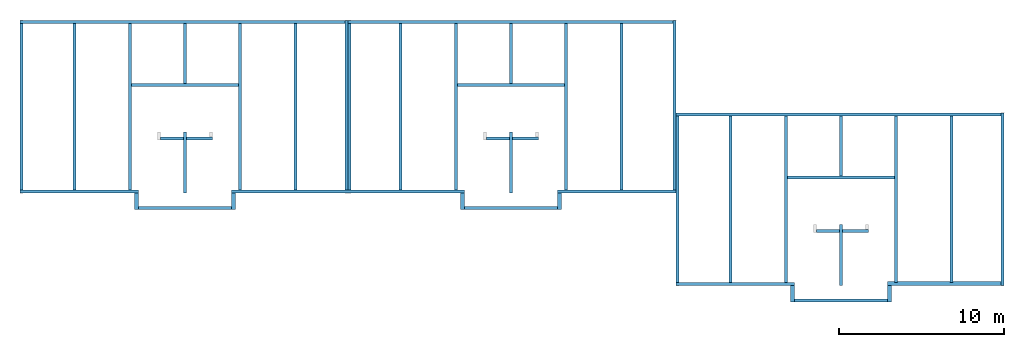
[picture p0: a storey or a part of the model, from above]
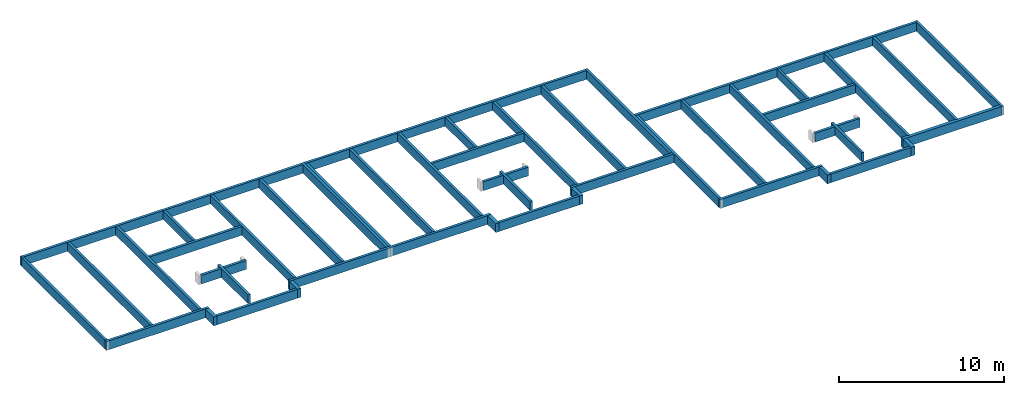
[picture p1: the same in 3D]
Properties of the parts of a building model (IFC2X3), part 1 of 3

# File
Description: IFC2x3 Coordination View
File name: C:\Users\jean-pierre\Desktop\acqs 2016.ifc
Time: 2016-04-21T13:30:04
Author: jean-pierre lafourcade
Organization: Nemetschek AG, Konrad-Zuse-Platz 1, 81829 Munich / Germany
Written by: The EXPRESS Data Manager Version 5.02.0100.02 : 29 May 2013
Made in: Allplan 2015.1 31.03.2015 - 10:33:38

# IfcBuildingStorey (5)
In: Bâtiment
Name | Elevation (mm)
vs | -850
rdc | 0
r+1 | 2700
r+2 | 5400
r+3 | 8100

# IfcOpeningElement: Opening (161)
Allplan Attributes - Object Layer Attributes #1, Catégorie de transformation: Nouvelle construction; Object Layer Attributes #1, Unité: m²
Name | In | Length (m) | Height (m) | GrossVolume (m3) | NominalArea (m2) | Object Layer Attributes #1, Métier = Object Layer Attributes #2, Métier | Object Layer Attributes #1, NOI_UUID | Object Layer Attributes #2, Unité = Object Layer Attributes #3, Unité | Object Layer Attributes #2, NOI_UUID | Object Layer Attributes #3, Métier | Object Layer Attributes #3, NOI_UUID
Baie de fenêtre | rdc | 0.6 | 0.34 | -0.03672 | -0.204 | Maçonnerie | 938c77c7-219d-4147-869d-5d58a54f96e7--5496 | m² | 938c77c7-219d-4147-869d-5d58a54f96e7--5497 | Enduits et plâtrages | 938c77c7-219d-4147-869d-5d58a54f96e7--5498
Baie de fenêtre | rdc | 0.6 | 0.34 | -0.03672 | -0.204 | Maçonnerie | 938c77c7-219d-4147-869d-5d58a54f96e7--5516 | m² | 938c77c7-219d-4147-869d-5d58a54f96e7--5517 | Enduits et plâtrages | 938c77c7-219d-4147-869d-5d58a54f96e7--5518
Baie de fenêtre | rdc | 1.8 | 1.15 | -0.3726 | -2.07 | Maçonnerie | 938c77c7-219d-4147-869d-5d58a54f96e7--5156 | m² | 938c77c7-219d-4147-869d-5d58a54f96e7--5157 | Enduits et plâtrages | 938c77c7-219d-4147-869d-5d58a54f96e7--5158
Baie de fenêtre | rdc | 1.8 | 1.15 | -0.3726 | -2.07 | Maçonnerie | 938c77c7-219d-4147-869d-5d58a54f96e7--5176 | m² | 938c77c7-219d-4147-869d-5d58a54f96e7--5177 | Enduits et plâtrages | 938c77c7-219d-4147-869d-5d58a54f96e7--5178
Baie de fenêtre | rdc | 1.8 | 1.15 | -0.3726 | -2.07 | Maçonnerie | 938c77c7-219d-4147-869d-5d58a54f96e7--5196 | m² | 938c77c7-219d-4147-869d-5d58a54f96e7--5197 | Enduits et plâtrages | 938c77c7-219d-4147-869d-5d58a54f96e7--5198
Baie de fenêtre | rdc | 1.8 | 1.15 | -0.3726 | -2.07 | Maçonnerie | 938c77c7-219d-4147-869d-5d58a54f96e7--5216 | m² | 938c77c7-219d-4147-869d-5d58a54f96e7--5217 | Enduits et plâtrages | 938c77c7-219d-4147-869d-5d58a54f96e7--5218
Baie de porte | rdc | 2.9 | 2.15 | -1.1223 | -6.235 | Maçonnerie | 938c77c7-219d-4147-869d-5d58a54f96e7--5356 | m² | 938c77c7-219d-4147-869d-5d58a54f96e7--5357 | Enduits et plâtrages | 938c77c7-219d-4147-869d-5d58a54f96e7--5358
Baie de porte | rdc | 2.9 | 2.15 | -1.1223 | -6.235 | Maçonnerie | 938c77c7-219d-4147-869d-5d58a54f96e7--5376 | m² | 938c77c7-219d-4147-869d-5d58a54f96e7--5377 | Enduits et plâtrages | 938c77c7-219d-4147-869d-5d58a54f96e7--5378
Baie de fenêtre | rdc | 1.8 | 1.15 | -0.3726 | -2.07 | Maçonnerie | 938c77c7-219d-4147-869d-5d58a54f96e7--5076 | m² | 938c77c7-219d-4147-869d-5d58a54f96e7--5077 | Enduits et plâtrages | 938c77c7-219d-4147-869d-5d58a54f96e7--5078
Baie de fenêtre | rdc | 1.8 | 1.15 | -0.3726 | -2.07 | Maçonnerie | 938c77c7-219d-4147-869d-5d58a54f96e7--5096 | m² | 938c77c7-219d-4147-869d-5d58a54f96e7--5097 | Enduits et plâtrages | 938c77c7-219d-4147-869d-5d58a54f96e7--5098
Baie de fenêtre | rdc | 1.8 | 1.15 | -0.3726 | -2.07 | Maçonnerie | 938c77c7-219d-4147-869d-5d58a54f96e7--5116 | m² | 938c77c7-219d-4147-869d-5d58a54f96e7--5117 | Enduits et plâtrages | 938c77c7-219d-4147-869d-5d58a54f96e7--5118
Baie de fenêtre | rdc | 1.8 | 1.15 | -0.3726 | -2.07 | Maçonnerie | 938c77c7-219d-4147-869d-5d58a54f96e7--5136 | m² | 938c77c7-219d-4147-869d-5d58a54f96e7--5137 | Enduits et plâtrages | 938c77c7-219d-4147-869d-5d58a54f96e7--5138
Baie de porte | rdc | 2.9 | 2.15 | -1.1223 | -6.235 | Maçonnerie | 938c77c7-219d-4147-869d-5d58a54f96e7--5316 | m² | 938c77c7-219d-4147-869d-5d58a54f96e7--5317 | Enduits et plâtrages | 938c77c7-219d-4147-869d-5d58a54f96e7--5318
Baie de porte | rdc | 2.9 | 2.15 | -1.1223 | -6.235 | Maçonnerie | 938c77c7-219d-4147-869d-5d58a54f96e7--5336 | m² | 938c77c7-219d-4147-869d-5d58a54f96e7--5337 | Enduits et plâtrages | 938c77c7-219d-4147-869d-5d58a54f96e7--5338
Baie de fenêtre | rdc | 1.8 | 1.15 | -0.3726 | -2.07 | Maçonnerie | 938c77c7-219d-4147-869d-5d58a54f96e7--5236 | m² | 938c77c7-219d-4147-869d-5d58a54f96e7--5237 | Enduits et plâtrages | 938c77c7-219d-4147-869d-5d58a54f96e7--5238
Baie de fenêtre | rdc | 1.8 | 1.15 | -0.3726 | -2.07 | Maçonnerie | 938c77c7-219d-4147-869d-5d58a54f96e7--5256 | m² | 938c77c7-219d-4147-869d-5d58a54f96e7--5257 | Enduits et plâtrages | 938c77c7-219d-4147-869d-5d58a54f96e7--5258
Baie de fenêtre | rdc | 1.8 | 1.15 | -0.3726 | -2.07 | Maçonnerie | 938c77c7-219d-4147-869d-5d58a54f96e7--5276 | m² | 938c77c7-219d-4147-869d-5d58a54f96e7--5277 | Enduits et plâtrages | 938c77c7-219d-4147-869d-5d58a54f96e7--5278
Baie de fenêtre | rdc | 1.8 | 1.15 | -0.3726 | -2.07 | Maçonnerie | 938c77c7-219d-4147-869d-5d58a54f96e7--5296 | m² | 938c77c7-219d-4147-869d-5d58a54f96e7--5297 | Enduits et plâtrages | 938c77c7-219d-4147-869d-5d58a54f96e7--5298
Baie de porte | rdc | 2.9 | 2.15 | -1.1223 | -6.235 | Maçonnerie | 938c77c7-219d-4147-869d-5d58a54f96e7--5396 | m² | 938c77c7-219d-4147-869d-5d58a54f96e7--5397 | Enduits et plâtrages | 938c77c7-219d-4147-869d-5d58a54f96e7--5398
Baie de porte | rdc | 2.9 | 2.15 | -1.1223 | -6.235 | Maçonnerie | 938c77c7-219d-4147-869d-5d58a54f96e7--5416 | m² | 938c77c7-219d-4147-869d-5d58a54f96e7--5417 | Enduits et plâtrages | 938c77c7-219d-4147-869d-5d58a54f96e7--5418
Baie de fenêtre | rdc | 1.8 | 1.15 | -0.3726 | -2.07 | Maçonnerie | 938c77c7-219d-4147-869d-5d58a54f96e7--4283 | m² | 938c77c7-219d-4147-869d-5d58a54f96e7--4284 | Enduits et plâtrages | 938c77c7-219d-4147-869d-5d58a54f96e7--4285
Baie de fenêtre | rdc | 1.8 | 1.15 | -0.3726 | -2.07 | Maçonnerie | 938c77c7-219d-4147-869d-5d58a54f96e7--4303 | m² | 938c77c7-219d-4147-869d-5d58a54f96e7--4304 | Enduits et plâtrages | 938c77c7-219d-4147-869d-5d58a54f96e7--4305
Baie de fenêtre | rdc | 0.6 | 0.34 | -0.03672 | -0.204 | Maçonnerie | 938c77c7-219d-4147-869d-5d58a54f96e7--5476 | m² | 938c77c7-219d-4147-869d-5d58a54f96e7--5477 | Enduits et plâtrages | 938c77c7-219d-4147-869d-5d58a54f96e7--5478
Baie de fenêtre | rdc | 1.3 | 0.34 | -0.07956 | -0.442 | Maçonnerie | 938c77c7-219d-4147-869d-5d58a54f96e7--5576 | m² | 938c77c7-219d-4147-869d-5d58a54f96e7--5577 | Enduits et plâtrages | 938c77c7-219d-4147-869d-5d58a54f96e7--5578
Baie de fenêtre | rdc | 1.8 | 1.15 | -0.3726 | -2.07 | Maçonnerie | 938c77c7-219d-4147-869d-5d58a54f96e7--4323 | m² | 938c77c7-219d-4147-869d-5d58a54f96e7--4324 | Enduits et plâtrages | 938c77c7-219d-4147-869d-5d58a54f96e7--4325
Baie de fenêtre | rdc | 1.8 | 1.15 | -0.3726 | -2.07 | Maçonnerie | 938c77c7-219d-4147-869d-5d58a54f96e7--4343 | m² | 938c77c7-219d-4147-869d-5d58a54f96e7--4344 | Enduits et plâtrages | 938c77c7-219d-4147-869d-5d58a54f96e7--4345
Baie de fenêtre | rdc | 1.8 | 1.15 | -0.3726 | -2.07 | Maçonnerie | 938c77c7-219d-4147-869d-5d58a54f96e7--4363 | m² | 938c77c7-219d-4147-869d-5d58a54f96e7--4364 | Enduits et plâtrages | 938c77c7-219d-4147-869d-5d58a54f96e7--4365
Baie de fenêtre | rdc | 1.8 | 1.15 | -0.3726 | -2.07 | Maçonnerie | 938c77c7-219d-4147-869d-5d58a54f96e7--5035 | m² | 938c77c7-219d-4147-869d-5d58a54f96e7--5036 | Enduits et plâtrages | 938c77c7-219d-4147-869d-5d58a54f96e7--5037
Baie de fenêtre | rdc | 1.8 | 1.15 | -0.3726 | -2.07 | Maçonnerie | 938c77c7-219d-4147-869d-5d58a54f96e7--5056 | m² | 938c77c7-219d-4147-869d-5d58a54f96e7--5057 | Enduits et plâtrages | 938c77c7-219d-4147-869d-5d58a54f96e7--5058
Baie de fenêtre | rdc | 0.6 | 0.34 | -0.03672 | -0.204 | Maçonnerie | 938c77c7-219d-4147-869d-5d58a54f96e7--5536 | m² | 938c77c7-219d-4147-869d-5d58a54f96e7--5537 | Enduits et plâtrages | 938c77c7-219d-4147-869d-5d58a54f96e7--5538
Baie de fenêtre | rdc | 1.3 | 0.34 | -0.07956 | -0.442 | Maçonnerie | 938c77c7-219d-4147-869d-5d58a54f96e7--5556 | m² | 938c77c7-219d-4147-869d-5d58a54f96e7--5557 | Enduits et plâtrages | 938c77c7-219d-4147-869d-5d58a54f96e7--5558
Baie de fenêtre | rdc | 0.6 | 0.34 | -0.03672 | -0.204 | Maçonnerie | 938c77c7-219d-4147-869d-5d58a54f96e7--5436 | m² | 938c77c7-219d-4147-869d-5d58a54f96e7--5437 | Enduits et plâtrages | 938c77c7-219d-4147-869d-5d58a54f96e7--5438
Baie de fenêtre | rdc | 0.6 | 0.34 | -0.03672 | -0.204 | Maçonnerie | 938c77c7-219d-4147-869d-5d58a54f96e7--5456 | m² | 938c77c7-219d-4147-869d-5d58a54f96e7--5457 | Enduits et plâtrages | 938c77c7-219d-4147-869d-5d58a54f96e7--5458
Baie de fenêtre | rdc | 1.8 | 1.15 | -0.3726 | -2.07 | Maçonnerie | 938c77c7-219d-4147-869d-5d58a54f96e7--4421 | m² | 938c77c7-219d-4147-869d-5d58a54f96e7--4422 | Enduits et plâtrages | 938c77c7-219d-4147-869d-5d58a54f96e7--4423
Baie de fenêtre | rdc | 1.8 | 1.15 | -0.3726 | -2.07 | Maçonnerie | 938c77c7-219d-4147-869d-5d58a54f96e7--4441 | m² | 938c77c7-219d-4147-869d-5d58a54f96e7--4442 | Enduits et plâtrages | 938c77c7-219d-4147-869d-5d58a54f96e7--4443
Baie de fenêtre | rdc | 1.8 | 1.15 | -0.3726 | -2.07 | Maçonnerie | 938c77c7-219d-4147-869d-5d58a54f96e7--4823 | m² | 938c77c7-219d-4147-869d-5d58a54f96e7--4824 | Enduits et plâtrages | 938c77c7-219d-4147-869d-5d58a54f96e7--4825
Baie de fenêtre | rdc | 1.8 | 1.15 | -0.3726 | -2.07 | Maçonnerie | 938c77c7-219d-4147-869d-5d58a54f96e7--4481 | m² | 938c77c7-219d-4147-869d-5d58a54f96e7--4482 | Enduits et plâtrages | 938c77c7-219d-4147-869d-5d58a54f96e7--4483
Baie de fenêtre | rdc | 1.8 | 1.15 | -0.3726 | -2.07 | Maçonnerie | 938c77c7-219d-4147-869d-5d58a54f96e7--4461 | m² | 938c77c7-219d-4147-869d-5d58a54f96e7--4462 | Enduits et plâtrages | 938c77c7-219d-4147-869d-5d58a54f96e7--4463
Baie de fenêtre | r+1 | 0.6 | 0.34 | -0.03672 | -0.204 | Maçonnerie | d80b2029-7616-407a-9da1-afa361a85c10--1853 | m² | d80b2029-7616-407a-9da1-afa361a85c10--1852 | Enduits et plâtrages | d80b2029-7616-407a-9da1-afa361a85c10--1851
Baie de fenêtre | r+1 | 0.6 | 0.34 | -0.03672 | -0.204 | Maçonnerie | d80b2029-7616-407a-9da1-afa361a85c10--1859 | m² | d80b2029-7616-407a-9da1-afa361a85c10--1858 | Enduits et plâtrages | d80b2029-7616-407a-9da1-afa361a85c10--1857
Baie de fenêtre | r+1 | 1.8 | 1.15 | -0.3726 | -2.07 | Maçonnerie | d80b2029-7616-407a-9da1-afa361a85c10--1739 | m² | d80b2029-7616-407a-9da1-afa361a85c10--1738 | Enduits et plâtrages | d80b2029-7616-407a-9da1-afa361a85c10--1737
Baie de fenêtre | r+1 | 1.8 | 1.15 | -0.3726 | -2.07 | Maçonnerie | d80b2029-7616-407a-9da1-afa361a85c10--1745 | m² | d80b2029-7616-407a-9da1-afa361a85c10--1744 | Enduits et plâtrages | d80b2029-7616-407a-9da1-afa361a85c10--1743
Baie de fenêtre | r+1 | 1.8 | 1.15 | -0.3726 | -2.07 | Maçonnerie | d80b2029-7616-407a-9da1-afa361a85c10--1751 | m² | d80b2029-7616-407a-9da1-afa361a85c10--1750 | Enduits et plâtrages | d80b2029-7616-407a-9da1-afa361a85c10--1749
Baie de fenêtre | r+1 | 1.8 | 1.15 | -0.3726 | -2.07 | Maçonnerie | d80b2029-7616-407a-9da1-afa361a85c10--1757 | m² | d80b2029-7616-407a-9da1-afa361a85c10--1756 | Enduits et plâtrages | d80b2029-7616-407a-9da1-afa361a85c10--1755
Baie de porte | r+1 | 2.9 | 2.15 | -1.1223 | -6.235 | Maçonnerie | d80b2029-7616-407a-9da1-afa361a85c10--1802 | m² | d80b2029-7616-407a-9da1-afa361a85c10--1801 | Enduits et plâtrages | d80b2029-7616-407a-9da1-afa361a85c10--1800
Baie de porte | r+1 | 2.9 | 2.15 | -1.1223 | -6.235 | Maçonnerie | d80b2029-7616-407a-9da1-afa361a85c10--1808 | m² | d80b2029-7616-407a-9da1-afa361a85c10--1807 | Enduits et plâtrages | d80b2029-7616-407a-9da1-afa361a85c10--1806
Baie de fenêtre | r+1 | 1.8 | 1.15 | -0.3726 | -2.07 | Maçonnerie | d80b2029-7616-407a-9da1-afa361a85c10--1715 | m² | d80b2029-7616-407a-9da1-afa361a85c10--1714 | Enduits et plâtrages | d80b2029-7616-407a-9da1-afa361a85c10--1713
Baie de fenêtre | r+1 | 1.8 | 1.15 | -0.3726 | -2.07 | Maçonnerie | d80b2029-7616-407a-9da1-afa361a85c10--1721 | m² | d80b2029-7616-407a-9da1-afa361a85c10--1720 | Enduits et plâtrages | d80b2029-7616-407a-9da1-afa361a85c10--1719
Baie de fenêtre | r+1 | 1.8 | 1.15 | -0.3726 | -2.07 | Maçonnerie | d80b2029-7616-407a-9da1-afa361a85c10--1727 | m² | d80b2029-7616-407a-9da1-afa361a85c10--1726 | Enduits et plâtrages | d80b2029-7616-407a-9da1-afa361a85c10--1725
Baie de fenêtre | r+1 | 1.8 | 1.15 | -0.3726 | -2.07 | Maçonnerie | d80b2029-7616-407a-9da1-afa361a85c10--1733 | m² | d80b2029-7616-407a-9da1-afa361a85c10--1732 | Enduits et plâtrages | d80b2029-7616-407a-9da1-afa361a85c10--1731
Baie de porte | r+1 | 2.9 | 2.15 | -1.1223 | -6.235 | Maçonnerie | d80b2029-7616-407a-9da1-afa361a85c10--1787 | m² | d80b2029-7616-407a-9da1-afa361a85c10--1786 | Enduits et plâtrages | d80b2029-7616-407a-9da1-afa361a85c10--1785
Baie de porte | r+1 | 2.9 | 2.15 | -1.1223 | -6.235 | Maçonnerie | d80b2029-7616-407a-9da1-afa361a85c10--1793 | m² | d80b2029-7616-407a-9da1-afa361a85c10--1792 | Enduits et plâtrages | d80b2029-7616-407a-9da1-afa361a85c10--1791
Baie de fenêtre | r+1 | 1.8 | 1.15 | -0.3726 | -2.07 | Maçonnerie | d80b2029-7616-407a-9da1-afa361a85c10--1763 | m² | d80b2029-7616-407a-9da1-afa361a85c10--1762 | Enduits et plâtrages | d80b2029-7616-407a-9da1-afa361a85c10--1761
Baie de fenêtre | r+1 | 1.8 | 1.15 | -0.3726 | -2.07 | Maçonnerie | d80b2029-7616-407a-9da1-afa361a85c10--1769 | m² | d80b2029-7616-407a-9da1-afa361a85c10--1768 | Enduits et plâtrages | d80b2029-7616-407a-9da1-afa361a85c10--1767
Baie de fenêtre | r+1 | 1.8 | 1.15 | -0.3726 | -2.07 | Maçonnerie | d80b2029-7616-407a-9da1-afa361a85c10--1775 | m² | d80b2029-7616-407a-9da1-afa361a85c10--1774 | Enduits et plâtrages | d80b2029-7616-407a-9da1-afa361a85c10--1773
Baie de fenêtre | r+1 | 1.8 | 1.15 | -0.3726 | -2.07 | Maçonnerie | d80b2029-7616-407a-9da1-afa361a85c10--1781 | m² | d80b2029-7616-407a-9da1-afa361a85c10--1780 | Enduits et plâtrages | d80b2029-7616-407a-9da1-afa361a85c10--1779
Baie de porte | r+1 | 2.9 | 2.15 | -1.1223 | -6.235 | Maçonnerie | d80b2029-7616-407a-9da1-afa361a85c10--1817 | m² | d80b2029-7616-407a-9da1-afa361a85c10--1816 | Enduits et plâtrages | d80b2029-7616-407a-9da1-afa361a85c10--1815
Baie de porte | r+1 | 2.9 | 2.15 | -1.1223 | -6.235 | Maçonnerie | d80b2029-7616-407a-9da1-afa361a85c10--1823 | m² | d80b2029-7616-407a-9da1-afa361a85c10--1822 | Enduits et plâtrages | d80b2029-7616-407a-9da1-afa361a85c10--1821
Baie de fenêtre | r+1 | 0.6 | 0.34 | -0.03672 | -0.204 | Maçonnerie | d80b2029-7616-407a-9da1-afa361a85c10--1847 | m² | d80b2029-7616-407a-9da1-afa361a85c10--1846 | Enduits et plâtrages | d80b2029-7616-407a-9da1-afa361a85c10--1845
Baie de fenêtre | r+1 | 1.3 | 0.34 | -0.07956 | -0.442 | Maçonnerie | d80b2029-7616-407a-9da1-afa361a85c10--1883 | m² | d80b2029-7616-407a-9da1-afa361a85c10--1882 | Enduits et plâtrages | d80b2029-7616-407a-9da1-afa361a85c10--1881
Baie de fenêtre | r+1 | 1.8 | 1.15 | -0.3726 | -2.07 | Maçonnerie | d80b2029-7616-407a-9da1-afa361a85c10--1555 | m² | d80b2029-7616-407a-9da1-afa361a85c10--1554 | Enduits et plâtrages | d80b2029-7616-407a-9da1-afa361a85c10--1553
Baie de fenêtre | r+1 | 1.8 | 1.15 | -0.3726 | -2.07 | Maçonnerie | d80b2029-7616-407a-9da1-afa361a85c10--1561 | m² | d80b2029-7616-407a-9da1-afa361a85c10--1560 | Enduits et plâtrages | d80b2029-7616-407a-9da1-afa361a85c10--1559
Baie de fenêtre | r+1 | 1.8 | 1.15 | -0.3726 | -2.07 | Maçonnerie | d80b2029-7616-407a-9da1-afa361a85c10--1567 | m² | d80b2029-7616-407a-9da1-afa361a85c10--1566 | Enduits et plâtrages | d80b2029-7616-407a-9da1-afa361a85c10--1565
Baie de fenêtre | r+1 | 1.8 | 1.15 | -0.3726 | -2.07 | Maçonnerie | d80b2029-7616-407a-9da1-afa361a85c10--1700 | m² | d80b2029-7616-407a-9da1-afa361a85c10--1699 | Enduits et plâtrages | d80b2029-7616-407a-9da1-afa361a85c10--1698
Baie de fenêtre | r+1 | 1.8 | 1.15 | -0.3726 | -2.07 | Maçonnerie | d80b2029-7616-407a-9da1-afa361a85c10--1709 | m² | d80b2029-7616-407a-9da1-afa361a85c10--1708 | Enduits et plâtrages | d80b2029-7616-407a-9da1-afa361a85c10--1707
Baie de fenêtre | r+1 | 0.6 | 0.34 | -0.03672 | -0.204 | Maçonnerie | d80b2029-7616-407a-9da1-afa361a85c10--1868 | m² | d80b2029-7616-407a-9da1-afa361a85c10--1867 | Enduits et plâtrages | d80b2029-7616-407a-9da1-afa361a85c10--1866
Baie de fenêtre | r+1 | 1.3 | 0.34 | -0.07956 | -0.442 | Maçonnerie | d80b2029-7616-407a-9da1-afa361a85c10--1874 | m² | d80b2029-7616-407a-9da1-afa361a85c10--1873 | Enduits et plâtrages | d80b2029-7616-407a-9da1-afa361a85c10--1872
Baie de fenêtre | r+1 | 0.6 | 0.34 | -0.03672 | -0.204 | Maçonnerie | d80b2029-7616-407a-9da1-afa361a85c10--1832 | m² | d80b2029-7616-407a-9da1-afa361a85c10--1831 | Enduits et plâtrages | d80b2029-7616-407a-9da1-afa361a85c10--1830
Baie de fenêtre | r+1 | 0.6 | 0.34 | -0.03672 | -0.204 | Maçonnerie | d80b2029-7616-407a-9da1-afa361a85c10--1838 | m² | d80b2029-7616-407a-9da1-afa361a85c10--1837 | Enduits et plâtrages | d80b2029-7616-407a-9da1-afa361a85c10--1836
Baie de fenêtre | r+1 | 1.8 | 1.15 | -0.3726 | -2.07 | Maçonnerie | d80b2029-7616-407a-9da1-afa361a85c10--1576 | m² | d80b2029-7616-407a-9da1-afa361a85c10--1575 | Enduits et plâtrages | d80b2029-7616-407a-9da1-afa361a85c10--1574
Baie de fenêtre | r+1 | 1.8 | 1.15 | -0.3726 | -2.07 | Maçonnerie | d80b2029-7616-407a-9da1-afa361a85c10--1582 | m² | d80b2029-7616-407a-9da1-afa361a85c10--1581 | Enduits et plâtrages | d80b2029-7616-407a-9da1-afa361a85c10--1580
Baie de fenêtre | r+1 | 1.8 | 1.15 | -0.3726 | -2.07 | Maçonnerie | d80b2029-7616-407a-9da1-afa361a85c10--1689 | m² | d80b2029-7616-407a-9da1-afa361a85c10--1690 | Enduits et plâtrages | d80b2029-7616-407a-9da1-afa361a85c10--1691
Baie de fenêtre | r+1 | 1.8 | 1.15 | -0.3726 | -2.07 | Maçonnerie | d80b2029-7616-407a-9da1-afa361a85c10--1666 | m² | d80b2029-7616-407a-9da1-afa361a85c10--1665 | Enduits et plâtrages | d80b2029-7616-407a-9da1-afa361a85c10--1664
Baie de fenêtre | r+1 | 1.8 | 1.15 | -0.3726 | -2.07 | Maçonnerie | d80b2029-7616-407a-9da1-afa361a85c10--1680 | m² | d80b2029-7616-407a-9da1-afa361a85c10--1681 | Enduits et plâtrages | d80b2029-7616-407a-9da1-afa361a85c10--1682
Baie de fenêtre | r+1 | 1.8 | 1.15 | -0.3726 | -2.07 | Maçonnerie | d80b2029-7616-407a-9da1-afa361a85c10--1546 | m² | d80b2029-7616-407a-9da1-afa361a85c10--1545 | Enduits et plâtrages | d80b2029-7616-407a-9da1-afa361a85c10--1544
Baie de fenêtre | r+1 | 1.8 | 1.15 | -0.3726 | -2.07 | Maçonnerie | d80b2029-7616-407a-9da1-afa361a85c10--1540 | m² | d80b2029-7616-407a-9da1-afa361a85c10--1539 | Enduits et plâtrages | d80b2029-7616-407a-9da1-afa361a85c10--1538
Trémie dans dalle | r+1 | 4.05 | 0.2 | -1.2555 | -6.2775 |  | d80b2029-7616-407a-9da1-afa361a85c10--641
Trémie dans dalle | r+1 | 4.05 | 0.2 | -1.2555 | -6.2775 |  | d80b2029-7616-407a-9da1-afa361a85c10--575
Trémie dans dalle | r+1 | 4.05 | 0.2 | -1.2555 | -6.2775 |  | d80b2029-7616-407a-9da1-afa361a85c10--580
Baie de fenêtre | r+2 | 0.6 | 0.34 | -0.03672 | -0.204 | Maçonnerie | 25afd9b5-9bbd-43b9-8fed-22435f7cc0c3--1191 | m² | 25afd9b5-9bbd-43b9-8fed-22435f7cc0c3--1190 | Enduits et plâtrages | 25afd9b5-9bbd-43b9-8fed-22435f7cc0c3--1189
Baie de fenêtre | r+2 | 0.6 | 0.34 | -0.03672 | -0.204 | Maçonnerie | 25afd9b5-9bbd-43b9-8fed-22435f7cc0c3--1194 | m² | 25afd9b5-9bbd-43b9-8fed-22435f7cc0c3--1193 | Enduits et plâtrages | 25afd9b5-9bbd-43b9-8fed-22435f7cc0c3--1192
Baie de fenêtre | r+2 | 1.8 | 1.15 | -0.3726 | -2.07 | Maçonnerie | 25afd9b5-9bbd-43b9-8fed-22435f7cc0c3--1140 | m² | 25afd9b5-9bbd-43b9-8fed-22435f7cc0c3--1139 | Enduits et plâtrages | 25afd9b5-9bbd-43b9-8fed-22435f7cc0c3--1138
Baie de fenêtre | r+2 | 1.8 | 1.15 | -0.3726 | -2.07 | Maçonnerie | 25afd9b5-9bbd-43b9-8fed-22435f7cc0c3--1143 | m² | 25afd9b5-9bbd-43b9-8fed-22435f7cc0c3--1142 | Enduits et plâtrages | 25afd9b5-9bbd-43b9-8fed-22435f7cc0c3--1141
Baie de fenêtre | r+2 | 1.8 | 1.15 | -0.3726 | -2.07 | Maçonnerie | 25afd9b5-9bbd-43b9-8fed-22435f7cc0c3--1146 | m² | 25afd9b5-9bbd-43b9-8fed-22435f7cc0c3--1145 | Enduits et plâtrages | 25afd9b5-9bbd-43b9-8fed-22435f7cc0c3--1144
Baie de fenêtre | r+2 | 1.8 | 1.15 | -0.3726 | -2.07 | Maçonnerie | 25afd9b5-9bbd-43b9-8fed-22435f7cc0c3--1149 | m² | 25afd9b5-9bbd-43b9-8fed-22435f7cc0c3--1148 | Enduits et plâtrages | 25afd9b5-9bbd-43b9-8fed-22435f7cc0c3--1147
Baie de porte | r+2 | 2.9 | 2.15 | -1.1223 | -6.235 | Maçonnerie | 25afd9b5-9bbd-43b9-8fed-22435f7cc0c3--1170 | m² | 25afd9b5-9bbd-43b9-8fed-22435f7cc0c3--1169 | Enduits et plâtrages | 25afd9b5-9bbd-43b9-8fed-22435f7cc0c3--1168
Baie de porte | r+2 | 2.9 | 2.15 | -1.1223 | -6.235 | Maçonnerie | 25afd9b5-9bbd-43b9-8fed-22435f7cc0c3--1173 | m² | 25afd9b5-9bbd-43b9-8fed-22435f7cc0c3--1172 | Enduits et plâtrages | 25afd9b5-9bbd-43b9-8fed-22435f7cc0c3--1171
Baie de fenêtre | r+2 | 1.8 | 1.15 | -0.3726 | -2.07 | Maçonnerie | 25afd9b5-9bbd-43b9-8fed-22435f7cc0c3--1128 | m² | 25afd9b5-9bbd-43b9-8fed-22435f7cc0c3--1127 | Enduits et plâtrages | 25afd9b5-9bbd-43b9-8fed-22435f7cc0c3--1126
Baie de fenêtre | r+2 | 1.8 | 1.15 | -0.3726 | -2.07 | Maçonnerie | 25afd9b5-9bbd-43b9-8fed-22435f7cc0c3--1131 | m² | 25afd9b5-9bbd-43b9-8fed-22435f7cc0c3--1130 | Enduits et plâtrages | 25afd9b5-9bbd-43b9-8fed-22435f7cc0c3--1129
Baie de fenêtre | r+2 | 1.8 | 1.15 | -0.3726 | -2.07 | Maçonnerie | 25afd9b5-9bbd-43b9-8fed-22435f7cc0c3--1134 | m² | 25afd9b5-9bbd-43b9-8fed-22435f7cc0c3--1133 | Enduits et plâtrages | 25afd9b5-9bbd-43b9-8fed-22435f7cc0c3--1132
Baie de fenêtre | r+2 | 1.8 | 1.15 | -0.3726 | -2.07 | Maçonnerie | 25afd9b5-9bbd-43b9-8fed-22435f7cc0c3--1137 | m² | 25afd9b5-9bbd-43b9-8fed-22435f7cc0c3--1136 | Enduits et plâtrages | 25afd9b5-9bbd-43b9-8fed-22435f7cc0c3--1135
Baie de porte | r+2 | 2.9 | 2.15 | -1.1223 | -6.235 | Maçonnerie | 25afd9b5-9bbd-43b9-8fed-22435f7cc0c3--1164 | m² | 25afd9b5-9bbd-43b9-8fed-22435f7cc0c3--1163 | Enduits et plâtrages | 25afd9b5-9bbd-43b9-8fed-22435f7cc0c3--1162
Baie de porte | r+2 | 2.9 | 2.15 | -1.1223 | -6.235 | Maçonnerie | 25afd9b5-9bbd-43b9-8fed-22435f7cc0c3--1167 | m² | 25afd9b5-9bbd-43b9-8fed-22435f7cc0c3--1166 | Enduits et plâtrages | 25afd9b5-9bbd-43b9-8fed-22435f7cc0c3--1165
Baie de fenêtre | r+2 | 1.8 | 1.15 | -0.3726 | -2.07 | Maçonnerie | 25afd9b5-9bbd-43b9-8fed-22435f7cc0c3--1152 | m² | 25afd9b5-9bbd-43b9-8fed-22435f7cc0c3--1151 | Enduits et plâtrages | 25afd9b5-9bbd-43b9-8fed-22435f7cc0c3--1150
Baie de fenêtre | r+2 | 1.8 | 1.15 | -0.3726 | -2.07 | Maçonnerie | 25afd9b5-9bbd-43b9-8fed-22435f7cc0c3--1155 | m² | 25afd9b5-9bbd-43b9-8fed-22435f7cc0c3--1154 | Enduits et plâtrages | 25afd9b5-9bbd-43b9-8fed-22435f7cc0c3--1153
Baie de fenêtre | r+2 | 1.8 | 1.15 | -0.3726 | -2.07 | Maçonnerie | 25afd9b5-9bbd-43b9-8fed-22435f7cc0c3--1158 | m² | 25afd9b5-9bbd-43b9-8fed-22435f7cc0c3--1157 | Enduits et plâtrages | 25afd9b5-9bbd-43b9-8fed-22435f7cc0c3--1156
Baie de fenêtre | r+2 | 1.8 | 1.15 | -0.3726 | -2.07 | Maçonnerie | 25afd9b5-9bbd-43b9-8fed-22435f7cc0c3--1161 | m² | 25afd9b5-9bbd-43b9-8fed-22435f7cc0c3--1160 | Enduits et plâtrages | 25afd9b5-9bbd-43b9-8fed-22435f7cc0c3--1159
Baie de porte | r+2 | 2.9 | 2.15 | -1.1223 | -6.235 | Maçonnerie | 25afd9b5-9bbd-43b9-8fed-22435f7cc0c3--1176 | m² | 25afd9b5-9bbd-43b9-8fed-22435f7cc0c3--1175 | Enduits et plâtrages | 25afd9b5-9bbd-43b9-8fed-22435f7cc0c3--1174
Baie de porte | r+2 | 2.9 | 2.15 | -1.1223 | -6.235 | Maçonnerie | 25afd9b5-9bbd-43b9-8fed-22435f7cc0c3--1179 | m² | 25afd9b5-9bbd-43b9-8fed-22435f7cc0c3--1178 | Enduits et plâtrages | 25afd9b5-9bbd-43b9-8fed-22435f7cc0c3--1177
Baie de fenêtre | r+2 | 0.6 | 0.34 | -0.03672 | -0.204 | Maçonnerie | 25afd9b5-9bbd-43b9-8fed-22435f7cc0c3--1188 | m² | 25afd9b5-9bbd-43b9-8fed-22435f7cc0c3--1187 | Enduits et plâtrages | 25afd9b5-9bbd-43b9-8fed-22435f7cc0c3--1186
Baie de fenêtre | r+2 | 1.3 | 0.34 | -0.07956 | -0.442 | Maçonnerie | 25afd9b5-9bbd-43b9-8fed-22435f7cc0c3--1203 | m² | 25afd9b5-9bbd-43b9-8fed-22435f7cc0c3--1202 | Enduits et plâtrages | 25afd9b5-9bbd-43b9-8fed-22435f7cc0c3--1201
Baie de fenêtre | r+2 | 1.8 | 1.15 | -0.3726 | -2.07 | Maçonnerie | 25afd9b5-9bbd-43b9-8fed-22435f7cc0c3--1098 | m² | 25afd9b5-9bbd-43b9-8fed-22435f7cc0c3--1097 | Enduits et plâtrages | 25afd9b5-9bbd-43b9-8fed-22435f7cc0c3--1096
Baie de fenêtre | r+2 | 1.8 | 1.15 | -0.3726 | -2.07 | Maçonnerie | 25afd9b5-9bbd-43b9-8fed-22435f7cc0c3--1101 | m² | 25afd9b5-9bbd-43b9-8fed-22435f7cc0c3--1100 | Enduits et plâtrages | 25afd9b5-9bbd-43b9-8fed-22435f7cc0c3--1099
Baie de fenêtre | r+2 | 1.8 | 1.15 | -0.3726 | -2.07 | Maçonnerie | 25afd9b5-9bbd-43b9-8fed-22435f7cc0c3--1104 | m² | 25afd9b5-9bbd-43b9-8fed-22435f7cc0c3--1103 | Enduits et plâtrages | 25afd9b5-9bbd-43b9-8fed-22435f7cc0c3--1102
Baie de fenêtre | r+2 | 1.8 | 1.15 | -0.3726 | -2.07 | Maçonnerie | 25afd9b5-9bbd-43b9-8fed-22435f7cc0c3--1122 | m² | 25afd9b5-9bbd-43b9-8fed-22435f7cc0c3--1121 | Enduits et plâtrages | 25afd9b5-9bbd-43b9-8fed-22435f7cc0c3--1120
Baie de fenêtre | r+2 | 1.8 | 1.15 | -0.3726 | -2.07 | Maçonnerie | 25afd9b5-9bbd-43b9-8fed-22435f7cc0c3--1125 | m² | 25afd9b5-9bbd-43b9-8fed-22435f7cc0c3--1124 | Enduits et plâtrages | 25afd9b5-9bbd-43b9-8fed-22435f7cc0c3--1123
Baie de fenêtre | r+2 | 0.6 | 0.34 | -0.03672 | -0.204 | Maçonnerie | 25afd9b5-9bbd-43b9-8fed-22435f7cc0c3--1197 | m² | 25afd9b5-9bbd-43b9-8fed-22435f7cc0c3--1196 | Enduits et plâtrages | 25afd9b5-9bbd-43b9-8fed-22435f7cc0c3--1195
Baie de fenêtre | r+2 | 1.3 | 0.34 | -0.07956 | -0.442 | Maçonnerie | 25afd9b5-9bbd-43b9-8fed-22435f7cc0c3--1200 | m² | 25afd9b5-9bbd-43b9-8fed-22435f7cc0c3--1199 | Enduits et plâtrages | 25afd9b5-9bbd-43b9-8fed-22435f7cc0c3--1198
Baie de fenêtre | r+2 | 0.6 | 0.34 | -0.03672 | -0.204 | Maçonnerie | 25afd9b5-9bbd-43b9-8fed-22435f7cc0c3--1182 | m² | 25afd9b5-9bbd-43b9-8fed-22435f7cc0c3--1181 | Enduits et plâtrages | 25afd9b5-9bbd-43b9-8fed-22435f7cc0c3--1180
Baie de fenêtre | r+2 | 0.6 | 0.34 | -0.03672 | -0.204 | Maçonnerie | 25afd9b5-9bbd-43b9-8fed-22435f7cc0c3--1185 | m² | 25afd9b5-9bbd-43b9-8fed-22435f7cc0c3--1184 | Enduits et plâtrages | 25afd9b5-9bbd-43b9-8fed-22435f7cc0c3--1183
Baie de fenêtre | r+2 | 1.8 | 1.15 | -0.3726 | -2.07 | Maçonnerie | 25afd9b5-9bbd-43b9-8fed-22435f7cc0c3--1107 | m² | 25afd9b5-9bbd-43b9-8fed-22435f7cc0c3--1106 | Enduits et plâtrages | 25afd9b5-9bbd-43b9-8fed-22435f7cc0c3--1105
Baie de fenêtre | r+2 | 1.8 | 1.15 | -0.3726 | -2.07 | Maçonnerie | 25afd9b5-9bbd-43b9-8fed-22435f7cc0c3--1110 | m² | 25afd9b5-9bbd-43b9-8fed-22435f7cc0c3--1109 | Enduits et plâtrages | 25afd9b5-9bbd-43b9-8fed-22435f7cc0c3--1108
Baie de fenêtre | r+2 | 1.8 | 1.15 | -0.3726 | -2.07 | Maçonnerie | 25afd9b5-9bbd-43b9-8fed-22435f7cc0c3--1117 | m² | 25afd9b5-9bbd-43b9-8fed-22435f7cc0c3--1118 | Enduits et plâtrages | 25afd9b5-9bbd-43b9-8fed-22435f7cc0c3--1119
Baie de fenêtre | r+2 | 1.8 | 1.15 | -0.3726 | -2.07 | Maçonnerie | 25afd9b5-9bbd-43b9-8fed-22435f7cc0c3--1113 | m² | 25afd9b5-9bbd-43b9-8fed-22435f7cc0c3--1112 | Enduits et plâtrages | 25afd9b5-9bbd-43b9-8fed-22435f7cc0c3--1111
Baie de fenêtre | r+2 | 1.8 | 1.15 | -0.3726 | -2.07 | Maçonnerie | 25afd9b5-9bbd-43b9-8fed-22435f7cc0c3--1114 | m² | 25afd9b5-9bbd-43b9-8fed-22435f7cc0c3--1115 | Enduits et plâtrages | 25afd9b5-9bbd-43b9-8fed-22435f7cc0c3--1116
Baie de fenêtre | r+2 | 1.8 | 1.15 | -0.3726 | -2.07 | Maçonnerie | 25afd9b5-9bbd-43b9-8fed-22435f7cc0c3--1090 | m² | 25afd9b5-9bbd-43b9-8fed-22435f7cc0c3--1091 | Enduits et plâtrages | 25afd9b5-9bbd-43b9-8fed-22435f7cc0c3--1092
Baie de fenêtre | r+2 | 1.8 | 1.15 | -0.3726 | -2.07 | Maçonnerie | 25afd9b5-9bbd-43b9-8fed-22435f7cc0c3--1093 | m² | 25afd9b5-9bbd-43b9-8fed-22435f7cc0c3--1094 | Enduits et plâtrages | 25afd9b5-9bbd-43b9-8fed-22435f7cc0c3--1095
Trémie dans dalle | r+2 | 4.05 | 0.2 | -1.2555 | -6.2775 |  | 25afd9b5-9bbd-43b9-8fed-22435f7cc0c3--2
Trémie dans dalle | r+2 | 4.05 | 0.2 | -1.2555 | -6.2775 |  | 25afd9b5-9bbd-43b9-8fed-22435f7cc0c3--51
Trémie dans dalle | r+2 | 4.05 | 0.2 | -1.2555 | -6.2775 |  | 25afd9b5-9bbd-43b9-8fed-22435f7cc0c3--4
Baie de fenêtre | r+3 | 0.6 | 0.34 | -0.03672 | -0.204 | Maçonnerie | a802760e-0c55-402d-9c1e-f3b9780ee869--1117 | m² | a802760e-0c55-402d-9c1e-f3b9780ee869--1116 | Enduits et plâtrages | a802760e-0c55-402d-9c1e-f3b9780ee869--1115
Baie de fenêtre | r+3 | 0.6 | 0.34 | -0.03672 | -0.204 | Maçonnerie | a802760e-0c55-402d-9c1e-f3b9780ee869--1114 | m² | a802760e-0c55-402d-9c1e-f3b9780ee869--1113 | Enduits et plâtrages | a802760e-0c55-402d-9c1e-f3b9780ee869--1112
Baie de porte | r+3 | 2.9 | 2.15 | -1.1223 | -6.235 | Maçonnerie | a802760e-0c55-402d-9c1e-f3b9780ee869--1096 | m² | a802760e-0c55-402d-9c1e-f3b9780ee869--1095 | Enduits et plâtrages | a802760e-0c55-402d-9c1e-f3b9780ee869--1094
Baie de porte | r+3 | 2.9 | 2.15 | -1.1223 | -6.235 | Maçonnerie | a802760e-0c55-402d-9c1e-f3b9780ee869--1093 | m² | a802760e-0c55-402d-9c1e-f3b9780ee869--1092 | Enduits et plâtrages | a802760e-0c55-402d-9c1e-f3b9780ee869--1091
Baie de fenêtre | r+3 | 1.8 | 1.15 | -0.3726 | -2.07 | Maçonnerie | a802760e-0c55-402d-9c1e-f3b9780ee869--1072 | m² | a802760e-0c55-402d-9c1e-f3b9780ee869--1071 | Enduits et plâtrages | a802760e-0c55-402d-9c1e-f3b9780ee869--1070
Baie de fenêtre | r+3 | 1.8 | 1.15 | -0.3726 | -2.07 | Maçonnerie | a802760e-0c55-402d-9c1e-f3b9780ee869--1069 | m² | a802760e-0c55-402d-9c1e-f3b9780ee869--1068 | Enduits et plâtrages | a802760e-0c55-402d-9c1e-f3b9780ee869--1067
Baie de fenêtre | r+3 | 1.8 | 1.15 | -0.3726 | -2.07 | Maçonnerie | a802760e-0c55-402d-9c1e-f3b9780ee869--1066 | m² | a802760e-0c55-402d-9c1e-f3b9780ee869--1065 | Enduits et plâtrages | a802760e-0c55-402d-9c1e-f3b9780ee869--1064
Baie de fenêtre | r+3 | 1.8 | 1.15 | -0.3726 | -2.07 | Maçonnerie | a802760e-0c55-402d-9c1e-f3b9780ee869--1063 | m² | a802760e-0c55-402d-9c1e-f3b9780ee869--1062 | Enduits et plâtrages | a802760e-0c55-402d-9c1e-f3b9780ee869--1061
Baie de fenêtre | r+3 | 1.8 | 1.15 | -0.3726 | -2.07 | Maçonnerie | a802760e-0c55-402d-9c1e-f3b9780ee869--1045 | m² | a802760e-0c55-402d-9c1e-f3b9780ee869--1044 | Enduits et plâtrages | a802760e-0c55-402d-9c1e-f3b9780ee869--1043
Baie de fenêtre | r+3 | 1.8 | 1.15 | -0.3726 | -2.07 | Maçonnerie | a802760e-0c55-402d-9c1e-f3b9780ee869--1027 | m² | a802760e-0c55-402d-9c1e-f3b9780ee869--1026 | Enduits et plâtrages | a802760e-0c55-402d-9c1e-f3b9780ee869--1025
Baie de fenêtre | r+3 | 1.8 | 1.15 | -0.3726 | -2.07 | Maçonnerie | a802760e-0c55-402d-9c1e-f3b9780ee869--1024 | m² | a802760e-0c55-402d-9c1e-f3b9780ee869--1023 | Enduits et plâtrages | a802760e-0c55-402d-9c1e-f3b9780ee869--1022
Baie de fenêtre | r+3 | 1.8 | 1.15 | -0.3726 | -2.07 | Maçonnerie | a802760e-0c55-402d-9c1e-f3b9780ee869--1021 | m² | a802760e-0c55-402d-9c1e-f3b9780ee869--1020 | Enduits et plâtrages | a802760e-0c55-402d-9c1e-f3b9780ee869--1019
Baie de fenêtre | r+3 | 1.3 | 0.34 | -0.07956 | -0.442 | Maçonnerie | a802760e-0c55-402d-9c1e-f3b9780ee869--1126 | m² | a802760e-0c55-402d-9c1e-f3b9780ee869--1125 | Enduits et plâtrages | a802760e-0c55-402d-9c1e-f3b9780ee869--1124
Baie de fenêtre | r+3 | 0.6 | 0.34 | -0.03672 | -0.204 | Maçonnerie | a802760e-0c55-402d-9c1e-f3b9780ee869--1111 | m² | a802760e-0c55-402d-9c1e-f3b9780ee869--1110 | Enduits et plâtrages | a802760e-0c55-402d-9c1e-f3b9780ee869--1109
Baie de fenêtre | r+3 | 0.6 | 0.34 | -0.03672 | -0.204 | Maçonnerie | a802760e-0c55-402d-9c1e-f3b9780ee869--1108 | m² | a802760e-0c55-402d-9c1e-f3b9780ee869--1107 | Enduits et plâtrages | a802760e-0c55-402d-9c1e-f3b9780ee869--1106
Baie de fenêtre | r+3 | 0.6 | 0.34 | -0.03672 | -0.204 | Maçonnerie | a802760e-0c55-402d-9c1e-f3b9780ee869--1105 | m² | a802760e-0c55-402d-9c1e-f3b9780ee869--1104 | Enduits et plâtrages | a802760e-0c55-402d-9c1e-f3b9780ee869--1103
Baie de porte | r+3 | 2.9 | 2.15 | -1.1223 | -6.235 | Maçonnerie | a802760e-0c55-402d-9c1e-f3b9780ee869--1102 | m² | a802760e-0c55-402d-9c1e-f3b9780ee869--1101 | Enduits et plâtrages | a802760e-0c55-402d-9c1e-f3b9780ee869--1100
Baie de porte | r+3 | 2.9 | 2.15 | -1.1223 | -6.235 | Maçonnerie | a802760e-0c55-402d-9c1e-f3b9780ee869--1099 | m² | a802760e-0c55-402d-9c1e-f3b9780ee869--1098 | Enduits et plâtrages | a802760e-0c55-402d-9c1e-f3b9780ee869--1097
Baie de fenêtre | r+3 | 1.8 | 1.15 | -0.3726 | -2.07 | Maçonnerie | a802760e-0c55-402d-9c1e-f3b9780ee869--1084 | m² | a802760e-0c55-402d-9c1e-f3b9780ee869--1083 | Enduits et plâtrages | a802760e-0c55-402d-9c1e-f3b9780ee869--1082
Baie de fenêtre | r+3 | 1.8 | 1.15 | -0.3726 | -2.07 | Maçonnerie | a802760e-0c55-402d-9c1e-f3b9780ee869--1081 | m² | a802760e-0c55-402d-9c1e-f3b9780ee869--1080 | Enduits et plâtrages | a802760e-0c55-402d-9c1e-f3b9780ee869--1079
Baie de fenêtre | r+3 | 1.8 | 1.15 | -0.3726 | -2.07 | Maçonnerie | a802760e-0c55-402d-9c1e-f3b9780ee869--1078 | m² | a802760e-0c55-402d-9c1e-f3b9780ee869--1077 | Enduits et plâtrages | a802760e-0c55-402d-9c1e-f3b9780ee869--1076
Baie de fenêtre | r+3 | 1.8 | 1.15 | -0.3726 | -2.07 | Maçonnerie | a802760e-0c55-402d-9c1e-f3b9780ee869--1075 | m² | a802760e-0c55-402d-9c1e-f3b9780ee869--1074 | Enduits et plâtrages | a802760e-0c55-402d-9c1e-f3b9780ee869--1073
Baie de fenêtre | r+3 | 1.3 | 0.34 | -0.07956 | -0.442 | Maçonnerie | a802760e-0c55-402d-9c1e-f3b9780ee869--1123 | m² | a802760e-0c55-402d-9c1e-f3b9780ee869--1122 | Enduits et plâtrages | a802760e-0c55-402d-9c1e-f3b9780ee869--1121
Baie de fenêtre | r+3 | 0.6 | 0.34 | -0.03672 | -0.204 | Maçonnerie | a802760e-0c55-402d-9c1e-f3b9780ee869--1120 | m² | a802760e-0c55-402d-9c1e-f3b9780ee869--1119 | Enduits et plâtrages | a802760e-0c55-402d-9c1e-f3b9780ee869--1118
Baie de fenêtre | r+3 | 1.8 | 1.15 | -0.3726 | -2.07 | Maçonnerie | a802760e-0c55-402d-9c1e-f3b9780ee869--1048 | m² | a802760e-0c55-402d-9c1e-f3b9780ee869--1047 | Enduits et plâtrages | a802760e-0c55-402d-9c1e-f3b9780ee869--1046
Baie de fenêtre | r+3 | 1.8 | 1.15 | -0.3726 | -2.07 | Maçonnerie | a802760e-0c55-402d-9c1e-f3b9780ee869--1033 | m² | a802760e-0c55-402d-9c1e-f3b9780ee869--1032 | Enduits et plâtrages | a802760e-0c55-402d-9c1e-f3b9780ee869--1031
Baie de fenêtre | r+3 | 1.8 | 1.15 | -0.3726 | -2.07 | Maçonnerie | a802760e-0c55-402d-9c1e-f3b9780ee869--1030 | m² | a802760e-0c55-402d-9c1e-f3b9780ee869--1029 | Enduits et plâtrages | a802760e-0c55-402d-9c1e-f3b9780ee869--1028
Baie de fenêtre | r+3 | 1.8 | 1.15 | -0.3726 | -2.07 | Maçonnerie | a802760e-0c55-402d-9c1e-f3b9780ee869--1040 | m² | a802760e-0c55-402d-9c1e-f3b9780ee869--1041 | Enduits et plâtrages | a802760e-0c55-402d-9c1e-f3b9780ee869--1042
Baie de fenêtre | r+3 | 1.8 | 1.15 | -0.3726 | -2.07 | Maçonnerie | a802760e-0c55-402d-9c1e-f3b9780ee869--1037 | m² | a802760e-0c55-402d-9c1e-f3b9780ee869--1038 | Enduits et plâtrages | a802760e-0c55-402d-9c1e-f3b9780ee869--1039
Baie de fenêtre | r+3 | 1.8 | 1.15 | -0.3726 | -2.07 | Maçonnerie | a802760e-0c55-402d-9c1e-f3b9780ee869--1036 | m² | a802760e-0c55-402d-9c1e-f3b9780ee869--1035 | Enduits et plâtrages | a802760e-0c55-402d-9c1e-f3b9780ee869--1034
Baie de fenêtre | r+3 | 1.8 | 1.15 | -0.3726 | -2.07 | Maçonnerie | a802760e-0c55-402d-9c1e-f3b9780ee869--1016 | m² | a802760e-0c55-402d-9c1e-f3b9780ee869--1017 | Enduits et plâtrages | a802760e-0c55-402d-9c1e-f3b9780ee869--1018
Baie de fenêtre | r+3 | 1.8 | 1.15 | -0.3726 | -2.07 | Maçonnerie | a802760e-0c55-402d-9c1e-f3b9780ee869--1013 | m² | a802760e-0c55-402d-9c1e-f3b9780ee869--1014 | Enduits et plâtrages | a802760e-0c55-402d-9c1e-f3b9780ee869--1015
Baie de porte | r+3 | 2.9 | 2.15 | -1.1223 | -6.235 | Maçonnerie | a802760e-0c55-402d-9c1e-f3b9780ee869--1090 | m² | a802760e-0c55-402d-9c1e-f3b9780ee869--1089 | Enduits et plâtrages | a802760e-0c55-402d-9c1e-f3b9780ee869--1088
Baie de porte | r+3 | 2.9 | 2.15 | -1.1223 | -6.235 | Maçonnerie | a802760e-0c55-402d-9c1e-f3b9780ee869--1087 | m² | a802760e-0c55-402d-9c1e-f3b9780ee869--1086 | Enduits et plâtrages | a802760e-0c55-402d-9c1e-f3b9780ee869--1085
Baie de fenêtre | r+3 | 1.8 | 1.15 | -0.3726 | -2.07 | Maçonnerie | a802760e-0c55-402d-9c1e-f3b9780ee869--1060 | m² | a802760e-0c55-402d-9c1e-f3b9780ee869--1059 | Enduits et plâtrages | a802760e-0c55-402d-9c1e-f3b9780ee869--1058
Baie de fenêtre | r+3 | 1.8 | 1.15 | -0.3726 | -2.07 | Maçonnerie | a802760e-0c55-402d-9c1e-f3b9780ee869--1057 | m² | a802760e-0c55-402d-9c1e-f3b9780ee869--1056 | Enduits et plâtrages | a802760e-0c55-402d-9c1e-f3b9780ee869--1055
Baie de fenêtre | r+3 | 1.8 | 1.15 | -0.3726 | -2.07 | Maçonnerie | a802760e-0c55-402d-9c1e-f3b9780ee869--1054 | m² | a802760e-0c55-402d-9c1e-f3b9780ee869--1053 | Enduits et plâtrages | a802760e-0c55-402d-9c1e-f3b9780ee869--1052
Baie de fenêtre | r+3 | 1.8 | 1.15 | -0.3726 | -2.07 | Maçonnerie | a802760e-0c55-402d-9c1e-f3b9780ee869--1051 | m² | a802760e-0c55-402d-9c1e-f3b9780ee869--1050 | Enduits et plâtrages | a802760e-0c55-402d-9c1e-f3b9780ee869--1049
Trémie dans dalle | r+3 | 4.05 | 0.2 | -1.2555 | -6.2775 |  | a802760e-0c55-402d-9c1e-f3b9780ee869--51
Trémie dans dalle | r+3 | 4.05 | 0.2 | -1.2555 | -6.2775 |  | a802760e-0c55-402d-9c1e-f3b9780ee869--3
Trémie dans dalle | r+3 | 4.05 | 0.2 | -1.2555 | -6.2775 |  | a802760e-0c55-402d-9c1e-f3b9780ee869--2

# IfcRoof
In: r+3
RoofQuantities - TotalSurfaceArea: 790.179 m2
Allplan Attributes - Object Layer Attributes #1, Catégorie de transformation: Nouvelle construction; Object Layer Attributes #1, Unité: m²; Object Layer Attributes #1, NOI_UUID: a802760e-0c55-402d-9c1e-f3b9780ee869--4606

# IfcSlab (26)
Name | In | PredefinedType | Material | GrossVolume (m3) | NetVolume (m3) | GrossSideArea (m2) | Width (m) | Catégorie de transformation | Unité | NOI_UUID
 | rdc | FLOOR | layer 200 mm | 43.9524 | 43.9524 | 219.762 | 0.2 | Nouvelle construction | m² | 938c77c7-219d-4147-869d-5d58a54f96e7--2948
 | rdc | FLOOR | layer 200 mm | 43.9532 | 43.9532 | 219.766 | 0.2 | Nouvelle construction | m² | 938c77c7-219d-4147-869d-5d58a54f96e7--2945
 | rdc | FLOOR | layer 200 mm | 43.9525 | 43.9525 | 219.763 | 0.2 | Nouvelle construction | m² | 938c77c7-219d-4147-869d-5d58a54f96e7--3973
 | r+1 | FLOOR | layer 200 mm | 1.2241 | 1.2241 | 6.12052 | 0.2 | Nouvelle construction | m² | d80b2029-7616-407a-9da1-afa361a85c10--679
 | r+1 | FLOOR | layer 200 mm | 42.7285 | 41.473 | 213.643 | 0.2 | Nouvelle construction | m² | d80b2029-7616-407a-9da1-afa361a85c10--642
 | r+1 | FLOOR | layer 200 mm | 1.2241 | 1.2241 | 6.12052 | 0.2 | Nouvelle construction | m² | d80b2029-7616-407a-9da1-afa361a85c10--668
 | r+1 | FLOOR | layer 200 mm | 1.2239 | 1.2239 | 6.11948 | 0.2 | Nouvelle construction | m² | d80b2029-7616-407a-9da1-afa361a85c10--674
 | r+1 | FLOOR | layer 200 mm | 42.7292 | 41.4737 | 213.646 | 0.2 | Nouvelle construction | m² | d80b2029-7616-407a-9da1-afa361a85c10--383
 | r+1 | FLOOR | layer 200 mm | 42.7286 | 41.4731 | 213.643 | 0.2 | Nouvelle construction | m² | d80b2029-7616-407a-9da1-afa361a85c10--385
 | r+2 | FLOOR | layer 200 mm | 42.7292 | 41.4737 | 213.646 | 0.2 | Nouvelle construction | m² | 25afd9b5-9bbd-43b9-8fed-22435f7cc0c3--3
 | r+2 | FLOOR | layer 200 mm | 42.7285 | 41.473 | 213.643 | 0.2 | Nouvelle construction | m² | 25afd9b5-9bbd-43b9-8fed-22435f7cc0c3--53
 | r+2 | FLOOR | layer 200 mm | 42.7284 | 41.4729 | 213.642 | 0.2 | Nouvelle construction | m² | 25afd9b5-9bbd-43b9-8fed-22435f7cc0c3--5
 | r+3 | FLOOR | layer 200 mm | 42.7285 | 41.473 | 213.643 | 0.2 | Nouvelle construction | m² | a802760e-0c55-402d-9c1e-f3b9780ee869--53
 | r+3 | FLOOR | layer 200 mm | 42.7286 | 41.4731 | 213.643 | 0.2 | Nouvelle construction | m² | a802760e-0c55-402d-9c1e-f3b9780ee869--7
 | r+3 | FLOOR | layer 200 mm | 42.7292 | 41.4737 | 213.646 | 0.2 | Nouvelle construction | m² | a802760e-0c55-402d-9c1e-f3b9780ee869--4
8 x  | r+3 | ROOF
 | r+3 | FLOOR | layer 200 mm | 41.4886 | 41.4886 | 207.443 | 0.2 | Nouvelle construction | m² | 7127c6e1-8021-4604-9aee-cd764f1e16a8--7
 | r+3 | FLOOR | layer 200 mm | 41.4885 | 41.4885 | 207.443 | 0.2 | Nouvelle construction | m² | 7127c6e1-8021-4604-9aee-cd764f1e16a8--54
 | r+3 | FLOOR | layer 200 mm | 41.4892 | 41.4892 | 207.446 | 0.2 | Nouvelle construction | m² | 7127c6e1-8021-4604-9aee-cd764f1e16a8--5

# IfcWallStandardCase (300)
Allplan Attributes - Unité: Qt; Object Layer Attributes #1, Catégorie de transformation: Nouvelle construction; Object Layer Attributes #1, Unité: m²; Object Layer Attributes #1, Métier: Maçonnerie
Name | In | Material | GrossVolume (m3) | NetVolume (m3) | GrossSideArea (m2) = NetSideArea (m2) | NominalLength (m) | NominalWidth (m) | GrossFootprintArea (m2) | NominalHeight (m) | NOI_UUID | Object Layer Attributes #1, NOI_UUID
 | vs | moellons 20.0776 mm | 0.00234907 | 0.00234907 | 0.0130504 | 0.02008 | 0.18 | 0.00361396 | 0.65 | 3bd912ba-d446-45e1-8efa-ed7aa0f8b4da--82 | 3bd912ba-d446-45e1-8efa-ed7aa0f8b4da--368
 | vs | moellons 20 mm | 0.00234 | 0.00234 | 0.013 | 0.02 | 0.18 | 0.0036 | 0.65 | 3bd912ba-d446-45e1-8efa-ed7aa0f8b4da--99 | 3bd912ba-d446-45e1-8efa-ed7aa0f8b4da--370
 | vs | moellons 180 mm | 1.18053 | 1.18053 | 6.5585 | 10.09 | 0.18 | 1.8162 | 0.65 | 3bd912ba-d446-45e1-8efa-ed7aa0f8b4da--34 | 3bd912ba-d446-45e1-8efa-ed7aa0f8b4da--362
 | vs | moellons 180 mm | 0.839475 | 0.839475 | 4.66375 | 7.175 | 0.18 | 1.2915 | 0.65 | 3bd912ba-d446-45e1-8efa-ed7aa0f8b4da--2 | 3bd912ba-d446-45e1-8efa-ed7aa0f8b4da--309
 | vs | moellons 180 mm | 1.20159 | 1.20159 | 6.6755 | 10.27 | 0.18 | 1.8486 | 0.65 | 3bd912ba-d446-45e1-8efa-ed7aa0f8b4da--4 | 3bd912ba-d446-45e1-8efa-ed7aa0f8b4da--378
 | vs | moellons 180 mm | 2.30139 | 2.30139 | 12.7855 | 19.67 | 0.18 | 3.5406 | 0.65 | 3bd912ba-d446-45e1-8efa-ed7aa0f8b4da--6 | 3bd912ba-d446-45e1-8efa-ed7aa0f8b4da--354
 | vs | moellons 180 mm | 1.18052 | 1.18052 | 6.55844 | 10.0899 | 0.18 | 1.81618 | 0.65 | 3bd912ba-d446-45e1-8efa-ed7aa0f8b4da--14 | 3bd912ba-d446-45e1-8efa-ed7aa0f8b4da--350
 | vs | moellons 180 mm | 1.20158 | 1.20158 | 6.67544 | 10.2699 | 0.18 | 1.84858 | 0.65 | 3bd912ba-d446-45e1-8efa-ed7aa0f8b4da--25 | 3bd912ba-d446-45e1-8efa-ed7aa0f8b4da--357
 | vs | moellons 180 mm | 1.65087 | 1.65087 | 9.1715 | 14.11 | 0.18 | 2.5398 | 0.65 | 3bd912ba-d446-45e1-8efa-ed7aa0f8b4da--61 | 3bd912ba-d446-45e1-8efa-ed7aa0f8b4da--313
 | vs | moellons 20 mm | 0.00234 | 0.00234 | 0.013 | 0.02 | 0.18 | 0.0036 | 0.65 | 3bd912ba-d446-45e1-8efa-ed7aa0f8b4da--101 | 3bd912ba-d446-45e1-8efa-ed7aa0f8b4da--380
 | vs | moellons 20 mm | 0.00234 | 0.00234 | 0.013 | 0.02 | 0.18 | 0.0036 | 0.65 | 3bd912ba-d446-45e1-8efa-ed7aa0f8b4da--103 | 3bd912ba-d446-45e1-8efa-ed7aa0f8b4da--369
 | vs | moellons 20 mm | 0.00234 | 0.00234 | 0.013 | 0.02 | 0.18 | 0.0036 | 0.65 | 3bd912ba-d446-45e1-8efa-ed7aa0f8b4da--105 | 3bd912ba-d446-45e1-8efa-ed7aa0f8b4da--379
 | vs | moellons 20.1628 mm | 0.00235905 | 0.00235905 | 0.0131058 | 0.02016 | 0.18 | 0.0036293 | 0.65 | 3bd912ba-d446-45e1-8efa-ed7aa0f8b4da--113 | 3bd912ba-d446-45e1-8efa-ed7aa0f8b4da--371
 | vs | moellons 20.1628 mm | 0.00235905 | 0.00235905 | 0.0131058 | 0.02016 | 0.18 | 0.0036293 | 0.65 | 3bd912ba-d446-45e1-8efa-ed7aa0f8b4da--115 | 3bd912ba-d446-45e1-8efa-ed7aa0f8b4da--372
 | vs | moellons 180 mm | 2.30139 | 2.30139 | 12.7855 | 19.67 | 0.18 | 3.5406 | 0.65 | 3bd912ba-d446-45e1-8efa-ed7aa0f8b4da--27 | 3bd912ba-d446-45e1-8efa-ed7aa0f8b4da--365
 | vs | moellons 180 mm | 1.18053 | 1.18053 | 6.5585 | 10.09 | 0.18 | 1.8162 | 0.65 | 3bd912ba-d446-45e1-8efa-ed7aa0f8b4da--117 | 3bd912ba-d446-45e1-8efa-ed7aa0f8b4da--363
 | vs | moellons 180 mm | 0.839475 | 0.839475 | 4.66375 | 7.175 | 0.18 | 1.2915 | 0.65 | 3bd912ba-d446-45e1-8efa-ed7aa0f8b4da--1 | 3bd912ba-d446-45e1-8efa-ed7aa0f8b4da--317
 | vs | moellons 180 mm | 1.18053 | 1.18053 | 6.5585 | 10.09 | 0.18 | 1.8162 | 0.65 | 3bd912ba-d446-45e1-8efa-ed7aa0f8b4da--131 | 3bd912ba-d446-45e1-8efa-ed7aa0f8b4da--333
 | vs | moellons 180 mm | 1.18052 | 1.18052 | 6.55844 | 10.0899 | 0.18 | 1.81618 | 0.65 | 3bd912ba-d446-45e1-8efa-ed7aa0f8b4da--136 | 3bd912ba-d446-45e1-8efa-ed7aa0f8b4da--335
 | vs | moellons 180 mm | 1.18052 | 1.18052 | 6.55844 | 10.0899 | 0.18 | 1.81618 | 0.65 | 3bd912ba-d446-45e1-8efa-ed7aa0f8b4da--140 | 3bd912ba-d446-45e1-8efa-ed7aa0f8b4da--364
 | vs | moellons 180 mm | 1.18052 | 1.18052 | 6.55844 | 10.0899 | 0.18 | 1.81618 | 0.65 | 3bd912ba-d446-45e1-8efa-ed7aa0f8b4da--144 | 3bd912ba-d446-45e1-8efa-ed7aa0f8b4da--351
 | vs | moellons 180 mm | 1.18052 | 1.18052 | 6.55844 | 10.0899 | 0.18 | 1.81618 | 0.65 | 3bd912ba-d446-45e1-8efa-ed7aa0f8b4da--148 | 3bd912ba-d446-45e1-8efa-ed7aa0f8b4da--326
 | vs | moellons 180 mm | 1.18053 | 1.18053 | 6.5585 | 10.09 | 0.18 | 1.8162 | 0.65 | 3bd912ba-d446-45e1-8efa-ed7aa0f8b4da--152 | 3bd912ba-d446-45e1-8efa-ed7aa0f8b4da--352
 | vs | moellons 180 mm | 1.18053 | 1.18053 | 6.5585 | 10.09 | 0.18 | 1.8162 | 0.65 | 3bd912ba-d446-45e1-8efa-ed7aa0f8b4da--156 | 3bd912ba-d446-45e1-8efa-ed7aa0f8b4da--353
 | vs | moellons 180 mm | 0.42588 | 0.42588 | 2.366 | 3.64 | 0.18 | 0.6552 | 0.65 | 3bd912ba-d446-45e1-8efa-ed7aa0f8b4da--178 | 3bd912ba-d446-45e1-8efa-ed7aa0f8b4da--332
 | vs | moellons 180 mm | 0.42588 | 0.42588 | 2.366 | 3.64 | 0.18 | 0.6552 | 0.65 | 3bd912ba-d446-45e1-8efa-ed7aa0f8b4da--183 | 3bd912ba-d446-45e1-8efa-ed7aa0f8b4da--325
 | vs | moellons 180 mm | 0.75465 | 0.75465 | 4.1925 | 6.45 | 0.18 | 1.161 | 0.65 | 3bd912ba-d446-45e1-8efa-ed7aa0f8b4da--194 | 3bd912ba-d446-45e1-8efa-ed7aa0f8b4da--334
 | vs | moellons 180 mm | 0.0585 | 0.0585 | 0.325 | 0.5 | 0.18 | 0.09 | 0.65 | 3bd912ba-d446-45e1-8efa-ed7aa0f8b4da--197 | 3bd912ba-d446-45e1-8efa-ed7aa0f8b4da--330
2 x  | vs | moellons 180 mm | 0.34749 | 0.34749 | 1.9305 | 2.97 | 0.18 | 0.5346 | 0.65 | 3bd912ba-d446-45e1-8efa-ed7aa0f8b4da--199 | 3bd912ba-d446-45e1-8efa-ed7aa0f8b4da--298
 | vs | moellons 180 mm | 0.03744 | 0.03744 | 0.208 | 0.32 | 0.18 | 0.0576 | 0.65 | 3bd912ba-d446-45e1-8efa-ed7aa0f8b4da--201 | 3bd912ba-d446-45e1-8efa-ed7aa0f8b4da--331
 | vs | moellons 180 mm | 0.75465 | 0.75465 | 4.1925 | 6.45 | 0.18 | 1.161 | 0.65 | 3bd912ba-d446-45e1-8efa-ed7aa0f8b4da--203 | 3bd912ba-d446-45e1-8efa-ed7aa0f8b4da--327
 | vs | moellons 180 mm | 0.0585 | 0.0585 | 0.325 | 0.5 | 0.18 | 0.09 | 0.65 | 3bd912ba-d446-45e1-8efa-ed7aa0f8b4da--205 | 3bd912ba-d446-45e1-8efa-ed7aa0f8b4da--328
2 x  | vs | moellons 180 mm | 0.34749 | 0.34749 | 1.9305 | 2.97 | 0.18 | 0.5346 | 0.65 | 3bd912ba-d446-45e1-8efa-ed7aa0f8b4da--207 | 3bd912ba-d446-45e1-8efa-ed7aa0f8b4da--296
 | vs | moellons 180 mm | 0.03744 | 0.03744 | 0.208 | 0.32 | 0.18 | 0.0576 | 0.65 | 3bd912ba-d446-45e1-8efa-ed7aa0f8b4da--209 | 3bd912ba-d446-45e1-8efa-ed7aa0f8b4da--329
 | vs | moellons 180 mm | 0.432905 | 0.432905 | 2.40503 | 3.70004 | 0.18 | 0.666007 | 0.65 | 3bd912ba-d446-45e1-8efa-ed7aa0f8b4da--177 | 3bd912ba-d446-45e1-8efa-ed7aa0f8b4da--299
 | vs | moellons 180 mm | 0.432905 | 0.432905 | 2.40503 | 3.70004 | 0.18 | 0.666007 | 0.65 | 3bd912ba-d446-45e1-8efa-ed7aa0f8b4da--182 | 3bd912ba-d446-45e1-8efa-ed7aa0f8b4da--297
 | vs | moellons 250 mm | 0.1625 | 0.1625 | 0.65 | 1 | 0.25 | 0.25 | 0.65 | 3bd912ba-d446-45e1-8efa-ed7aa0f8b4da--97 | 3bd912ba-d446-45e1-8efa-ed7aa0f8b4da--381
 | vs | moellons 250 mm | 0.162486 | 0.162486 | 0.649944 | 0.99991 | 0.25 | 0.249979 | 0.65 | 3bd912ba-d446-45e1-8efa-ed7aa0f8b4da--259 | 3bd912ba-d446-45e1-8efa-ed7aa0f8b4da--308
 | vs | moellons 250 mm | 0.1625 | 0.1625 | 0.65 | 1 | 0.25 | 0.25 | 0.65 | 3bd912ba-d446-45e1-8efa-ed7aa0f8b4da--229 | 3bd912ba-d446-45e1-8efa-ed7aa0f8b4da--316
 | vs | moellons 250 mm | 0.162514 | 0.162514 | 0.650055 | 1.00009 | 0.25 | 0.250021 | 0.65 | 3bd912ba-d446-45e1-8efa-ed7aa0f8b4da--250 | 3bd912ba-d446-45e1-8efa-ed7aa0f8b4da--312
 | vs | moellons 20.0776 mm | 0.00234907 | 0.00234907 | 0.0130504 | 0.02008 | 0.18 | 0.00361396 | 0.65 | 3bd912ba-d446-45e1-8efa-ed7aa0f8b4da--2144 | 3bd912ba-d446-45e1-8efa-ed7aa0f8b4da--2225
 | vs | moellons 180 mm | 1.18053 | 1.18053 | 6.5585 | 10.09 | 0.18 | 1.8162 | 0.65 | 3bd912ba-d446-45e1-8efa-ed7aa0f8b4da--2148 | 3bd912ba-d446-45e1-8efa-ed7aa0f8b4da--2224
 | vs | moellons 180 mm | 1.22264 | 1.22264 | 6.79244 | 10.4499 | 0.18 | 1.88098 | 0.65 | 3bd912ba-d446-45e1-8efa-ed7aa0f8b4da--2155 | 3bd912ba-d446-45e1-8efa-ed7aa0f8b4da--2220
 | vs | moellons 20 mm | 0.00234 | 0.00234 | 0.013 | 0.02 | 0.18 | 0.0036 | 0.65 | 3bd912ba-d446-45e1-8efa-ed7aa0f8b4da--2161 | 3bd912ba-d446-45e1-8efa-ed7aa0f8b4da--2206
 | vs | moellons 20.1628 mm | 0.00235905 | 0.00235905 | 0.0131058 | 0.02016 | 0.18 | 0.0036293 | 0.65 | 3bd912ba-d446-45e1-8efa-ed7aa0f8b4da--2165 | 3bd912ba-d446-45e1-8efa-ed7aa0f8b4da--2222
 | vs | moellons 180 mm | 2.30139 | 2.30139 | 12.7855 | 19.67 | 0.18 | 3.5406 | 0.65 | 3bd912ba-d446-45e1-8efa-ed7aa0f8b4da--2167 | 3bd912ba-d446-45e1-8efa-ed7aa0f8b4da--2205
 | vs | moellons 180 mm | 1.18053 | 1.18053 | 6.5585 | 10.09 | 0.18 | 1.8162 | 0.65 | 3bd912ba-d446-45e1-8efa-ed7aa0f8b4da--2169 | 3bd912ba-d446-45e1-8efa-ed7aa0f8b4da--2226
 | vs | moellons 180 mm | 0.839475 | 0.839475 | 4.66375 | 7.175 | 0.18 | 1.2915 | 0.65 | 3bd912ba-d446-45e1-8efa-ed7aa0f8b4da--2171 | 3bd912ba-d446-45e1-8efa-ed7aa0f8b4da--2217
 | vs | moellons 180 mm | 1.18053 | 1.18053 | 6.5585 | 10.09 | 0.18 | 1.8162 | 0.65 | 3bd912ba-d446-45e1-8efa-ed7aa0f8b4da--2173 | 3bd912ba-d446-45e1-8efa-ed7aa0f8b4da--2227
 | vs | moellons 180 mm | 1.18052 | 1.18052 | 6.55844 | 10.0899 | 0.18 | 1.81618 | 0.65 | 3bd912ba-d446-45e1-8efa-ed7aa0f8b4da--2175 | 3bd912ba-d446-45e1-8efa-ed7aa0f8b4da--2218
 | vs | moellons 180 mm | 1.18052 | 1.18052 | 6.55844 | 10.0899 | 0.18 | 1.81618 | 0.65 | 3bd912ba-d446-45e1-8efa-ed7aa0f8b4da--2177 | 3bd912ba-d446-45e1-8efa-ed7aa0f8b4da--2219
 | vs | moellons 180 mm | 0.42588 | 0.42588 | 2.366 | 3.64 | 0.18 | 0.6552 | 0.65 | 3bd912ba-d446-45e1-8efa-ed7aa0f8b4da--2180 | 3bd912ba-d446-45e1-8efa-ed7aa0f8b4da--2202
 | vs | moellons 180 mm | 0.75465 | 0.75465 | 4.1925 | 6.45 | 0.18 | 1.161 | 0.65 | 3bd912ba-d446-45e1-8efa-ed7aa0f8b4da--2184 | 3bd912ba-d446-45e1-8efa-ed7aa0f8b4da--2203
 | vs | moellons 180 mm | 0.0585 | 0.0585 | 0.325 | 0.5 | 0.18 | 0.09 | 0.65 | 3bd912ba-d446-45e1-8efa-ed7aa0f8b4da--2186 | 3bd912ba-d446-45e1-8efa-ed7aa0f8b4da--2199
2 x  | vs | moellons 180 mm | 0.34749 | 0.34749 | 1.9305 | 2.97 | 0.18 | 0.5346 | 0.65 | 3bd912ba-d446-45e1-8efa-ed7aa0f8b4da--2188 | 3bd912ba-d446-45e1-8efa-ed7aa0f8b4da--2195
 | vs | moellons 180 mm | 0.03744 | 0.03744 | 0.208 | 0.32 | 0.18 | 0.0576 | 0.65 | 3bd912ba-d446-45e1-8efa-ed7aa0f8b4da--2190 | 3bd912ba-d446-45e1-8efa-ed7aa0f8b4da--2200
 | vs | moellons 180 mm | 0.432905 | 0.432905 | 2.40503 | 3.70004 | 0.18 | 0.666007 | 0.65 | 3bd912ba-d446-45e1-8efa-ed7aa0f8b4da--2192 | 3bd912ba-d446-45e1-8efa-ed7aa0f8b4da--2196
 | vs | moellons 250 mm | 0.1625 | 0.1625 | 0.65 | 1 | 0.25 | 0.25 | 0.65 | 3bd912ba-d446-45e1-8efa-ed7aa0f8b4da--2209 | 3bd912ba-d446-45e1-8efa-ed7aa0f8b4da--2216
 | vs | moellons 250 mm | 0.162514 | 0.162514 | 0.650055 | 1.00009 | 0.25 | 0.250021 | 0.65 | 3bd912ba-d446-45e1-8efa-ed7aa0f8b4da--2212 | 3bd912ba-d446-45e1-8efa-ed7aa0f8b4da--2214
 | vs | moellons 180 mm, briquettes 40 mm, enduit platre 10 mm | 1.01611 | 1.01611 |  | 6.635 | 0.23 | 1.56325 | 0.65 | 3bd912ba-d446-45e1-8efa-ed7aa0f8b4da--2157 | 3bd912ba-d446-45e1-8efa-ed7aa0f8b4da--2215 | WallQuantities - GrossSideAreaRight: 4.46875 m2; GrossSideAreaLeft: 4.23475 m2; NetSideAreaRight: 4.46875 m2; NetSideAreaLeft: 4.23475 m2; Allplan Attributes - Object Layer Attributes #2, Unité: m²; Object Layer Attributes #2, Métier: Maçonnerie; Object Layer Attributes #2, NOI_UUID: 3bd912ba-d446-45e1-8efa-ed7aa0f8b4da--2438; Object Layer Attributes #3, Unité: m²; Object Layer Attributes #3, Métier: Enduits et plâtrages; Object Layer Attributes #3, NOI_UUID: 3bd912ba-d446-45e1-8efa-ed7aa0f8b4da--2439
 | vs | moellons 180 mm | 0.65754 | 0.65754 | 3.653 | 5.62 | 0.18 | 1.0116 | 0.65 | 3bd912ba-d446-45e1-8efa-ed7aa0f8b4da--2822 | 3bd912ba-d446-45e1-8efa-ed7aa0f8b4da--2823
 | vs | moellons 180 mm | 0.65754 | 0.65754 | 3.653 | 5.62 | 0.18 | 1.0116 | 0.65 | 3bd912ba-d446-45e1-8efa-ed7aa0f8b4da--2839 | 3bd912ba-d446-45e1-8efa-ed7aa0f8b4da--2840
 | vs | moellons 180 mm | 0.65754 | 0.65754 | 3.653 | 5.62 | 0.18 | 1.0116 | 0.65 | 3bd912ba-d446-45e1-8efa-ed7aa0f8b4da--2854 | 3bd912ba-d446-45e1-8efa-ed7aa0f8b4da--2855
 | rdc | moellons 180 mm, briquettes 40 mm, enduit platre 10 mm | 5.8765 | 5.78266 |  | 10.1067 | 0.23 | 2.3506 | 2.5 | 938c77c7-219d-4147-869d-5d58a54f96e7--244 | 938c77c7-219d-4147-869d-5d58a54f96e7--245 | WallQuantities - GrossSideAreaRight: 25.675 m2; GrossSideAreaLeft: 25 m2; NetSideAreaRight: 25.267 m2; NetSideAreaLeft: 24.592 m2; Allplan Attributes - Object Layer Attributes #2, Unité: m²; Object Layer Attributes #2, Métier: Maçonnerie; Object Layer Attributes #2, NOI_UUID: 938c77c7-219d-4147-869d-5d58a54f96e7--246; Object Layer Attributes #3, Unité: m²; Object Layer Attributes #3, Métier: Enduits et plâtrages; Object Layer Attributes #3, NOI_UUID: 938c77c7-219d-4147-869d-5d58a54f96e7--247
 | rdc | moellons 180 mm, briquettes 40 mm, enduit platre 10 mm | 11.169 | 6.3965 |  | 18.9067 | 0.23 | 4.4676 | 2.5 | 938c77c7-219d-4147-869d-5d58a54f96e7--277 | 938c77c7-219d-4147-869d-5d58a54f96e7--278 | WallQuantities - GrossSideAreaRight: 49.175 m2; GrossSideAreaLeft: 46.25 m2; NetSideAreaRight: 28.425 m2; NetSideAreaLeft: 25.5 m2; Allplan Attributes - Object Layer Attributes #2, Unité: m²; Object Layer Attributes #2, Métier: Maçonnerie; Object Layer Attributes #2, NOI_UUID: 938c77c7-219d-4147-869d-5d58a54f96e7--279; Object Layer Attributes #3, Unité: m²; Object Layer Attributes #3, Métier: Enduits et plâtrages; Object Layer Attributes #3, NOI_UUID: 938c77c7-219d-4147-869d-5d58a54f96e7--280
 | rdc | moellons 180 mm, briquettes 40 mm, enduit platre 10 mm | 5.7912 | 5.7912 |  | 10.0299 | 0.23 | 2.31648 | 2.5 | 938c77c7-219d-4147-869d-5d58a54f96e7--316 | 938c77c7-219d-4147-869d-5d58a54f96e7--317 | WallQuantities - GrossSideAreaRight: 25.2248 m2; GrossSideAreaLeft: 24.9748 m2; NetSideAreaRight: 25.2248 m2; NetSideAreaLeft: 24.9748 m2; Allplan Attributes - Object Layer Attributes #2, Unité: m²; Object Layer Attributes #2, Métier: Maçonnerie; Object Layer Attributes #2, NOI_UUID: 938c77c7-219d-4147-869d-5d58a54f96e7--318; Object Layer Attributes #3, Unité: m²; Object Layer Attributes #3, Métier: Enduits et plâtrages; Object Layer Attributes #3, NOI_UUID: 938c77c7-219d-4147-869d-5d58a54f96e7--319
 | rdc | moellons 180 mm, briquettes 40 mm, enduit platre 10 mm | 5.7912 | 5.7912 |  | 10.0299 | 0.23 | 2.31648 | 2.5 | 938c77c7-219d-4147-869d-5d58a54f96e7--377 | 938c77c7-219d-4147-869d-5d58a54f96e7--378 | WallQuantities - GrossSideAreaRight: 25.2248 m2; GrossSideAreaLeft: 24.9748 m2; NetSideAreaRight: 25.2248 m2; NetSideAreaLeft: 24.9748 m2; Allplan Attributes - Object Layer Attributes #2, Unité: m²; Object Layer Attributes #2, Métier: Maçonnerie; Object Layer Attributes #2, NOI_UUID: 938c77c7-219d-4147-869d-5d58a54f96e7--379; Object Layer Attributes #3, Unité: m²; Object Layer Attributes #3, Métier: Enduits et plâtrages; Object Layer Attributes #3, NOI_UUID: 938c77c7-219d-4147-869d-5d58a54f96e7--380
 | rdc | moellons 180 mm, briquettes 40 mm, enduit platre 10 mm | 11.2542 | 6.48175 |  | 18.9833 | 0.23 | 4.5017 | 2.5 | 938c77c7-219d-4147-869d-5d58a54f96e7--428 | 938c77c7-219d-4147-869d-5d58a54f96e7--429 | WallQuantities - GrossSideAreaRight: 49.625 m2; GrossSideAreaLeft: 46.275 m2; NetSideAreaRight: 28.875 m2; NetSideAreaLeft: 25.525 m2; Allplan Attributes - Object Layer Attributes #2, Unité: m²; Object Layer Attributes #2, Métier: Maçonnerie; Object Layer Attributes #2, NOI_UUID: 938c77c7-219d-4147-869d-5d58a54f96e7--430; Object Layer Attributes #3, Unité: m²; Object Layer Attributes #3, Métier: Enduits et plâtrages; Object Layer Attributes #3, NOI_UUID: 938c77c7-219d-4147-869d-5d58a54f96e7--431
 | rdc | moellons 20.0776 mm | 0.0090349 | 0.0090349 | 0.0501939 | 0.02008 | 0.18 | 0.00361396 | 2.5 | 938c77c7-219d-4147-869d-5d58a54f96e7--1643 | 938c77c7-219d-4147-869d-5d58a54f96e7--1644
 | rdc | moellons 20 mm | 0.009 | 0.009 | 0.05 | 0.02 | 0.18 | 0.0036 | 2.5 | 938c77c7-219d-4147-869d-5d58a54f96e7--1867 | 938c77c7-219d-4147-869d-5d58a54f96e7--1868
 | rdc | moellons 20 mm | 0.009 | 0.009 | 0.05 | 0.02 | 0.18 | 0.0036 | 2.5 | 938c77c7-219d-4147-869d-5d58a54f96e7--1898 | 938c77c7-219d-4147-869d-5d58a54f96e7--1899
 | rdc | moellons 20 mm | 0.009 | 0.009 | 0.05 | 0.02 | 0.18 | 0.0036 | 2.5 | 938c77c7-219d-4147-869d-5d58a54f96e7--1907 | 938c77c7-219d-4147-869d-5d58a54f96e7--1908
 | rdc | moellons 20 mm | 0.009 | 0.009 | 0.05 | 0.02 | 0.18 | 0.0036 | 2.5 | 938c77c7-219d-4147-869d-5d58a54f96e7--1917 | 938c77c7-219d-4147-869d-5d58a54f96e7--1918
 | rdc | moellons 20.1628 mm | 0.00907326 | 0.00907326 | 0.050407 | 0.02016 | 0.18 | 0.0036293 | 2.5 | 938c77c7-219d-4147-869d-5d58a54f96e7--1987 | 938c77c7-219d-4147-869d-5d58a54f96e7--1988
 | rdc | moellons 20.1628 mm | 0.00907326 | 0.00907326 | 0.050407 | 0.02016 | 0.18 | 0.0036293 | 2.5 | 938c77c7-219d-4147-869d-5d58a54f96e7--2023 | 938c77c7-219d-4147-869d-5d58a54f96e7--2024
 | rdc | moellons 180 mm | 4.5405 | 4.5405 | 25.225 | 10.09 | 0.18 | 1.8162 | 2.5 | 938c77c7-219d-4147-869d-5d58a54f96e7--2061 | 938c77c7-219d-4147-869d-5d58a54f96e7--2062
 | rdc | moellons 180 mm | 4.5405 | 4.5405 | 25.225 | 10.09 | 0.18 | 1.8162 | 2.5 | 938c77c7-219d-4147-869d-5d58a54f96e7--2208 | 938c77c7-219d-4147-869d-5d58a54f96e7--2209
 | rdc | moellons 180 mm | 4.5405 | 4.5405 | 25.225 | 10.09 | 0.18 | 1.8162 | 2.5 | 938c77c7-219d-4147-869d-5d58a54f96e7--2342 | 938c77c7-219d-4147-869d-5d58a54f96e7--2346
 | rdc | moellons 180 mm | 4.5405 | 4.5405 | 25.225 | 10.09 | 0.18 | 1.8162 | 2.5 | 938c77c7-219d-4147-869d-5d58a54f96e7--2367 | 938c77c7-219d-4147-869d-5d58a54f96e7--2369
 | rdc | moellons 180 mm | 4.5405 | 4.5405 | 25.225 | 10.09 | 0.18 | 1.8162 | 2.5 | 938c77c7-219d-4147-869d-5d58a54f96e7--2389 | 938c77c7-219d-4147-869d-5d58a54f96e7--2391
 | rdc | moellons 180 mm | 4.5405 | 4.5405 | 25.225 | 10.09 | 0.18 | 1.8162 | 2.5 | 938c77c7-219d-4147-869d-5d58a54f96e7--2411 | 938c77c7-219d-4147-869d-5d58a54f96e7--2413
 | rdc | moellons 180 mm | 4.5405 | 4.5405 | 25.225 | 10.09 | 0.18 | 1.8162 | 2.5 | 938c77c7-219d-4147-869d-5d58a54f96e7--2446 | 938c77c7-219d-4147-869d-5d58a54f96e7--2448
 | rdc | moellons 180 mm | 4.5405 | 4.5405 | 25.225 | 10.09 | 0.18 | 1.8162 | 2.5 | 938c77c7-219d-4147-869d-5d58a54f96e7--2467 | 938c77c7-219d-4147-869d-5d58a54f96e7--2469
2 x  | rdc | moellons 180 mm | 1.58402 | 1.58402 | 8.8001 | 3.52004 | 0.18 | 0.633607 | 2.5 | 938c77c7-219d-4147-869d-5d58a54f96e7--2584 | 938c77c7-219d-4147-869d-5d58a54f96e7--2586
 | rdc | moellons 180 mm | 1.638 | 1.638 | 9.1 | 3.64 | 0.18 | 0.6552 | 2.5 | 938c77c7-219d-4147-869d-5d58a54f96e7--2599 | 938c77c7-219d-4147-869d-5d58a54f96e7--2601
2 x  | rdc | moellons 180 mm | 1.58402 | 1.58402 | 8.8001 | 3.52004 | 0.18 | 0.633607 | 2.5 | 938c77c7-219d-4147-869d-5d58a54f96e7--2433 | 938c77c7-219d-4147-869d-5d58a54f96e7--2435
 | rdc | moellons 180 mm | 1.638 | 1.638 | 9.1 | 3.64 | 0.18 | 0.6552 | 2.5 | 938c77c7-219d-4147-869d-5d58a54f96e7--2642 | 938c77c7-219d-4147-869d-5d58a54f96e7--2644
 | rdc | moellons 180 mm | 2.9025 | 2.9025 | 16.125 | 6.45 | 0.18 | 1.161 | 2.5 | 938c77c7-219d-4147-869d-5d58a54f96e7--2720 | 938c77c7-219d-4147-869d-5d58a54f96e7--2721
 | rdc | moellons 180 mm | 0.225 | 0.225 | 1.25 | 0.5 | 0.18 | 0.09 | 2.5 | 938c77c7-219d-4147-869d-5d58a54f96e7--2738 | 938c77c7-219d-4147-869d-5d58a54f96e7--2739
 | rdc | moellons 180 mm | 1.4175 | 1.4175 | 7.875 | 3.15 | 0.18 | 0.567 | 2.5 | 938c77c7-219d-4147-869d-5d58a54f96e7--2743 | 938c77c7-219d-4147-869d-5d58a54f96e7--2744
 | rdc | moellons 180 mm | 0.144 | 0.144 | 0.8 | 0.32 | 0.18 | 0.0576 | 2.5 | 938c77c7-219d-4147-869d-5d58a54f96e7--2756 | 938c77c7-219d-4147-869d-5d58a54f96e7--2757
 | rdc | moellons 180 mm | 2.9025 | 2.9025 | 16.125 | 6.45 | 0.18 | 1.161 | 2.5 | 938c77c7-219d-4147-869d-5d58a54f96e7--2770 | 938c77c7-219d-4147-869d-5d58a54f96e7--2771
 | rdc | moellons 180 mm | 0.225 | 0.225 | 1.25 | 0.5 | 0.18 | 0.09 | 2.5 | 938c77c7-219d-4147-869d-5d58a54f96e7--2773 | 938c77c7-219d-4147-869d-5d58a54f96e7--2780
 | rdc | moellons 180 mm | 1.4175 | 1.4175 | 7.875 | 3.15 | 0.18 | 0.567 | 2.5 | 938c77c7-219d-4147-869d-5d58a54f96e7--2775 | 938c77c7-219d-4147-869d-5d58a54f96e7--2778
 | rdc | moellons 180 mm | 0.144 | 0.144 | 0.8 | 0.32 | 0.18 | 0.0576 | 2.5 | 938c77c7-219d-4147-869d-5d58a54f96e7--2777 | 938c77c7-219d-4147-869d-5d58a54f96e7--2779
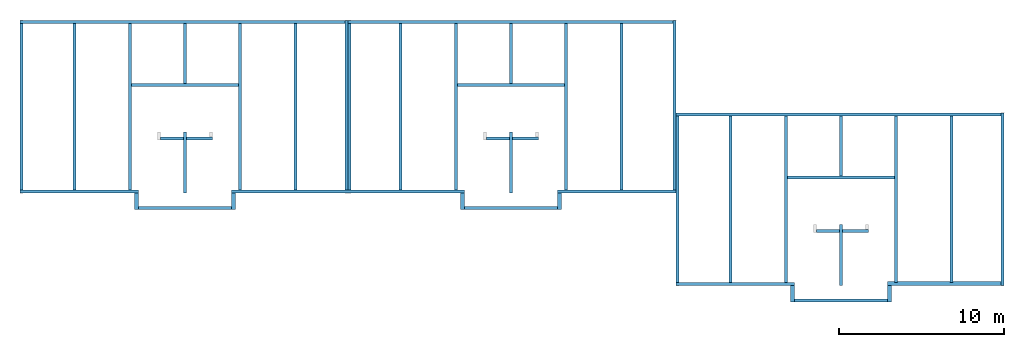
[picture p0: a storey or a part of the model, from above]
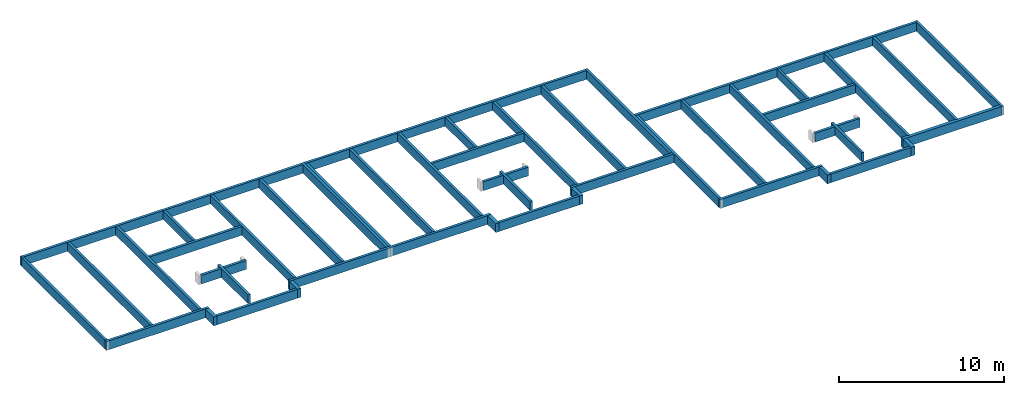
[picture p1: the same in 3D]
Properties of the parts of a building model (IFC2X3), part 2 of 3

# IfcWallStandardCase (300)
Name | In | Material | GrossVolume (m3) | NetVolume (m3) | GrossSideArea (m2) = NetSideArea (m2) | NominalLength (m) | NominalWidth (m) | GrossFootprintArea (m2) | NominalHeight (m) | NOI_UUID | Object Layer Attributes #1, NOI_UUID
 | rdc | moellons 180 mm, briquettes 40 mm, enduit platre 10 mm | 11.2542 | 6.48175 |  | 18.9833 | 0.23 | 4.5017 | 2.5 | 938c77c7-219d-4147-869d-5d58a54f96e7--3846 | 938c77c7-219d-4147-869d-5d58a54f96e7--4004 | WallQuantities - GrossSideAreaRight: 49.625 m2; GrossSideAreaLeft: 46.275 m2; NetSideAreaRight: 28.875 m2; NetSideAreaLeft: 25.525 m2; Allplan Attributes - Object Layer Attributes #2, Unité: m²; Object Layer Attributes #2, Métier: Maçonnerie; Object Layer Attributes #2, NOI_UUID: 938c77c7-219d-4147-869d-5d58a54f96e7--4006; Object Layer Attributes #3, Unité: m²; Object Layer Attributes #3, Métier: Enduits et plâtrages; Object Layer Attributes #3, NOI_UUID: 938c77c7-219d-4147-869d-5d58a54f96e7--4005
 | rdc | moellons 20.0776 mm | 0.0090349 | 0.0090349 | 0.0501939 | 0.02008 | 0.18 | 0.00361396 | 2.5 | 938c77c7-219d-4147-869d-5d58a54f96e7--3875 | 938c77c7-219d-4147-869d-5d58a54f96e7--4007
 | rdc | moellons 20 mm | 0.009 | 0.009 | 0.05 | 0.02 | 0.18 | 0.0036 | 2.5 | 938c77c7-219d-4147-869d-5d58a54f96e7--3881 | 938c77c7-219d-4147-869d-5d58a54f96e7--4008
 | rdc | moellons 20.1628 mm | 0.00907326 | 0.00907326 | 0.050407 | 0.02016 | 0.18 | 0.0036293 | 2.5 | 938c77c7-219d-4147-869d-5d58a54f96e7--3885 | 938c77c7-219d-4147-869d-5d58a54f96e7--4011
 | rdc | moellons 180 mm | 4.5405 | 4.5405 | 25.225 | 10.09 | 0.18 | 1.8162 | 2.5 | 938c77c7-219d-4147-869d-5d58a54f96e7--3887 | 938c77c7-219d-4147-869d-5d58a54f96e7--4002
 | rdc | moellons 180 mm | 4.5405 | 4.5405 | 25.225 | 10.09 | 0.18 | 1.8162 | 2.5 | 938c77c7-219d-4147-869d-5d58a54f96e7--3901 | 938c77c7-219d-4147-869d-5d58a54f96e7--3987
 | rdc | moellons 180 mm | 4.54046 | 4.54046 | 25.2248 | 10.0899 | 0.18 | 1.81618 | 2.5 | 938c77c7-219d-4147-869d-5d58a54f96e7--3906 | 938c77c7-219d-4147-869d-5d58a54f96e7--3989
 | rdc | moellons 180 mm | 4.54046 | 4.54046 | 25.2248 | 10.0899 | 0.18 | 1.81618 | 2.5 | 938c77c7-219d-4147-869d-5d58a54f96e7--3910 | 938c77c7-219d-4147-869d-5d58a54f96e7--4003
2 x  | rdc | moellons 180 mm | 1.58402 | 1.58402 | 8.8001 | 3.52004 | 0.18 | 0.633607 | 2.5 | 938c77c7-219d-4147-869d-5d58a54f96e7--3922 | 938c77c7-219d-4147-869d-5d58a54f96e7--3975
 | rdc | moellons 180 mm | 1.638 | 1.638 | 9.1 | 3.64 | 0.18 | 0.6552 | 2.5 | 938c77c7-219d-4147-869d-5d58a54f96e7--3923 | 938c77c7-219d-4147-869d-5d58a54f96e7--3986
 | rdc | moellons 180 mm | 2.9025 | 2.9025 | 16.125 | 6.45 | 0.18 | 1.161 | 2.5 | 938c77c7-219d-4147-869d-5d58a54f96e7--3931 | 938c77c7-219d-4147-869d-5d58a54f96e7--3988
 | rdc | moellons 180 mm | 0.225 | 0.225 | 1.25 | 0.5 | 0.18 | 0.09 | 2.5 | 938c77c7-219d-4147-869d-5d58a54f96e7--3934 | 938c77c7-219d-4147-869d-5d58a54f96e7--3984
 | rdc | moellons 180 mm | 1.4175 | 1.4175 | 7.875 | 3.15 | 0.18 | 0.567 | 2.5 | 938c77c7-219d-4147-869d-5d58a54f96e7--3936 | 938c77c7-219d-4147-869d-5d58a54f96e7--3974
 | rdc | moellons 180 mm | 0.144 | 0.144 | 0.8 | 0.32 | 0.18 | 0.0576 | 2.5 | 938c77c7-219d-4147-869d-5d58a54f96e7--3938 | 938c77c7-219d-4147-869d-5d58a54f96e7--3985
 | rdc | moellons 180 mm, briquettes 40 mm, enduit platre 10 mm | 4.05713 | 3.10493 |  | 6.80167 | 0.23 | 1.62285 | 2.5 | 938c77c7-219d-4147-869d-5d58a54f96e7--200 | 938c77c7-219d-4147-869d-5d58a54f96e7--201 | WallQuantities - GrossSideAreaRight: 17.9375 m2; GrossSideAreaLeft: 16.4875 m2; NetSideAreaRight: 13.7975 m2; NetSideAreaLeft: 12.3475 m2; Allplan Attributes - Object Layer Attributes #2, Unité: m²; Object Layer Attributes #2, Métier: Maçonnerie; Object Layer Attributes #2, NOI_UUID: 938c77c7-219d-4147-869d-5d58a54f96e7--202; Object Layer Attributes #3, Unité: m²; Object Layer Attributes #3, Métier: Enduits et plâtrages; Object Layer Attributes #3, NOI_UUID: 938c77c7-219d-4147-869d-5d58a54f96e7--203
 | rdc | moellons 180 mm, briquettes 40 mm, enduit platre 10 mm | 5.79125 | 5.64267 |  | 10.03 | 0.23 | 2.3165 | 2.5 | 938c77c7-219d-4147-869d-5d58a54f96e7--460 | 938c77c7-219d-4147-869d-5d58a54f96e7--461 | WallQuantities - GrossSideAreaRight: 25.225 m2; GrossSideAreaLeft: 24.975 m2; NetSideAreaRight: 24.579 m2; NetSideAreaLeft: 24.329 m2; Allplan Attributes - Object Layer Attributes #2, Unité: m²; Object Layer Attributes #2, Métier: Maçonnerie; Object Layer Attributes #2, NOI_UUID: 938c77c7-219d-4147-869d-5d58a54f96e7--462; Object Layer Attributes #3, Unité: m²; Object Layer Attributes #3, Métier: Enduits et plâtrages; Object Layer Attributes #3, NOI_UUID: 938c77c7-219d-4147-869d-5d58a54f96e7--463
 | rdc | moellons 180 mm, briquettes 40 mm, enduit platre 10 mm | 7.9761 | 6.0717 |  | 13.3632 | 0.23 | 3.19044 | 2.5 | 938c77c7-219d-4147-869d-5d58a54f96e7--222 | 938c77c7-219d-4147-869d-5d58a54f96e7--223 | WallQuantities - GrossSideAreaRight: 35.2741 m2; GrossSideAreaLeft: 32.375 m2; NetSideAreaRight: 26.995 m2; NetSideAreaLeft: 24.095 m2; Allplan Attributes - Object Layer Attributes #2, Unité: m²; Object Layer Attributes #2, Métier: Maçonnerie; Object Layer Attributes #2, NOI_UUID: 938c77c7-219d-4147-869d-5d58a54f96e7--224; Object Layer Attributes #3, Unité: m²; Object Layer Attributes #3, Métier: Enduits et plâtrages; Object Layer Attributes #3, NOI_UUID: 938c77c7-219d-4147-869d-5d58a54f96e7--225
 | rdc | moellons 180 mm, briquettes 40 mm, enduit platre 10 mm | 5.7912 | 5.16652 |  | 10.0299 | 0.23 | 2.31648 | 2.5 | 938c77c7-219d-4147-869d-5d58a54f96e7--3844 | 938c77c7-219d-4147-869d-5d58a54f96e7--3996 | WallQuantities - GrossSideAreaRight: 25.2248 m2; GrossSideAreaLeft: 24.9748 m2; NetSideAreaRight: 22.5088 m2; NetSideAreaLeft: 22.2588 m2; Allplan Attributes - Object Layer Attributes #2, Unité: m²; Object Layer Attributes #2, Métier: Maçonnerie; Object Layer Attributes #2, NOI_UUID: 938c77c7-219d-4147-869d-5d58a54f96e7--3997; Object Layer Attributes #3, Unité: m²; Object Layer Attributes #3, Métier: Enduits et plâtrages; Object Layer Attributes #3, NOI_UUID: 938c77c7-219d-4147-869d-5d58a54f96e7--3998
 | rdc | moellons 180 mm, briquettes 40 mm, enduit platre 10 mm | 5.79125 | 5.69741 |  | 10.03 | 0.23 | 2.3165 | 2.5 | 938c77c7-219d-4147-869d-5d58a54f96e7--3853 | 938c77c7-219d-4147-869d-5d58a54f96e7--4001 | WallQuantities - GrossSideAreaRight: 25.225 m2; GrossSideAreaLeft: 24.975 m2; NetSideAreaRight: 24.817 m2; NetSideAreaLeft: 24.567 m2; Allplan Attributes - Object Layer Attributes #2, Unité: m²; Object Layer Attributes #2, Métier: Maçonnerie; Object Layer Attributes #2, NOI_UUID: 938c77c7-219d-4147-869d-5d58a54f96e7--4000; Object Layer Attributes #3, Unité: m²; Object Layer Attributes #3, Métier: Enduits et plâtrages; Object Layer Attributes #3, NOI_UUID: 938c77c7-219d-4147-869d-5d58a54f96e7--3999
 | rdc | moellons 180 mm, briquettes 40 mm, enduit platre 10 mm | 4.05712 | 3.10492 |  | 6.80167 | 0.23 | 1.62285 | 2.5 | 938c77c7-219d-4147-869d-5d58a54f96e7--233 | 938c77c7-219d-4147-869d-5d58a54f96e7--234 | WallQuantities - GrossSideAreaRight: 17.9375 m2; GrossSideAreaLeft: 16.4875 m2; NetSideAreaRight: 13.7975 m2; NetSideAreaLeft: 12.3475 m2; Allplan Attributes - Object Layer Attributes #2, Unité: m²; Object Layer Attributes #2, Métier: Maçonnerie; Object Layer Attributes #2, NOI_UUID: 938c77c7-219d-4147-869d-5d58a54f96e7--235; Object Layer Attributes #3, Unité: m²; Object Layer Attributes #3, Métier: Enduits et plâtrages; Object Layer Attributes #3, NOI_UUID: 938c77c7-219d-4147-869d-5d58a54f96e7--236; Object Layer Attributes #1, Matériau: moellons
 | rdc | moellons 180 mm, briquettes 40 mm, enduit platre 10 mm | 3.98812 | 3.51202 |  | 6.68167 | 0.23 | 1.59525 | 2.5 | 938c77c7-219d-4147-869d-5d58a54f96e7--4501 | 938c77c7-219d-4147-869d-5d58a54f96e7--4521 | WallQuantities - GrossSideAreaRight: 17.6375 m2; GrossSideAreaLeft: 16.1875 m2; NetSideAreaRight: 15.5675 m2; NetSideAreaLeft: 14.1175 m2; Allplan Attributes - Object Layer Attributes #2, Unité: m²; Object Layer Attributes #2, Métier: Maçonnerie; Object Layer Attributes #2, NOI_UUID: 938c77c7-219d-4147-869d-5d58a54f96e7--4523; Object Layer Attributes #3, Unité: m²; Object Layer Attributes #3, Métier: Enduits et plâtrages; Object Layer Attributes #3, NOI_UUID: 938c77c7-219d-4147-869d-5d58a54f96e7--4522; Object Layer Attributes #1, Matériau: moellons
 | rdc | moellons 180 mm, briquettes 40 mm, enduit platre 10 mm | 4.05713 | 3.10493 |  | 6.80167 | 0.23 | 1.62285 | 2.5 | 938c77c7-219d-4147-869d-5d58a54f96e7--3824 | 938c77c7-219d-4147-869d-5d58a54f96e7--3981 | WallQuantities - GrossSideAreaRight: 17.9375 m2; GrossSideAreaLeft: 16.4875 m2; NetSideAreaRight: 13.7975 m2; NetSideAreaLeft: 12.3475 m2; Allplan Attributes - Object Layer Attributes #2, Unité: m²; Object Layer Attributes #2, Métier: Maçonnerie; Object Layer Attributes #2, NOI_UUID: 938c77c7-219d-4147-869d-5d58a54f96e7--3982; Object Layer Attributes #3, Unité: m²; Object Layer Attributes #3, Métier: Enduits et plâtrages; Object Layer Attributes #3, NOI_UUID: 938c77c7-219d-4147-869d-5d58a54f96e7--3983
 | rdc | moellons 250 mm | 0.575 | 0.575 | 2.3 | 1 | 0.25 | 0.25 | 2.3 | 938c77c7-219d-4147-869d-5d58a54f96e7--2831 | 938c77c7-219d-4147-869d-5d58a54f96e7--2832 | Allplan Attributes - Object Layer Attributes #1, Matériau: moellons
 | rdc | moellons 250 mm | 0.575 | 0.575 | 2.3 | 1 | 0.25 | 0.25 | 2.3 | 938c77c7-219d-4147-869d-5d58a54f96e7--2848 | 938c77c7-219d-4147-869d-5d58a54f96e7--2849
 | rdc | moellons 250 mm | 0.575 | 0.575 | 2.3 | 1 | 0.25 | 0.25 | 2.3 | 938c77c7-219d-4147-869d-5d58a54f96e7--1795 | 938c77c7-219d-4147-869d-5d58a54f96e7--1796
 | rdc | moellons 250 mm | 0.574951 | 0.574951 | 2.2998 | 0.99991 | 0.25 | 0.249979 | 2.3 | 938c77c7-219d-4147-869d-5d58a54f96e7--2864 | 938c77c7-219d-4147-869d-5d58a54f96e7--2865
 | rdc | moellons 250 mm | 0.575 | 0.575 | 2.3 | 1 | 0.25 | 0.25 | 2.3 | 938c77c7-219d-4147-869d-5d58a54f96e7--3969 | 938c77c7-219d-4147-869d-5d58a54f96e7--3976
 | rdc | moellons 250 mm | 0.575 | 0.575 | 2.3 | 1 | 0.25 | 0.25 | 2.3 | 938c77c7-219d-4147-869d-5d58a54f96e7--3948 | 938c77c7-219d-4147-869d-5d58a54f96e7--3980
 | r+1 | moellons 180 mm, briquettes 40 mm, enduit platre 10 mm | 5.8765 | 5.78266 |  | 10.1067 | 0.23 | 2.3506 | 2.5 | d80b2029-7616-407a-9da1-afa361a85c10--1301 | d80b2029-7616-407a-9da1-afa361a85c10--1861 | WallQuantities - GrossSideAreaRight: 25.675 m2; GrossSideAreaLeft: 25 m2; NetSideAreaRight: 25.267 m2; NetSideAreaLeft: 24.592 m2; Allplan Attributes - Object Layer Attributes #2, Unité: m²; Object Layer Attributes #2, Métier: Maçonnerie; Object Layer Attributes #2, NOI_UUID: d80b2029-7616-407a-9da1-afa361a85c10--1863; Object Layer Attributes #3, Unité: m²; Object Layer Attributes #3, Métier: Enduits et plâtrages; Object Layer Attributes #3, NOI_UUID: d80b2029-7616-407a-9da1-afa361a85c10--1862
 | r+1 | moellons 180 mm, briquettes 40 mm, enduit platre 10 mm | 11.169 | 6.3965 |  | 18.9067 | 0.23 | 4.4676 | 2.5 | d80b2029-7616-407a-9da1-afa361a85c10--1303 | d80b2029-7616-407a-9da1-afa361a85c10--1810 | WallQuantities - GrossSideAreaRight: 49.175 m2; GrossSideAreaLeft: 46.25 m2; NetSideAreaRight: 28.425 m2; NetSideAreaLeft: 25.5 m2; Allplan Attributes - Object Layer Attributes #2, Unité: m²; Object Layer Attributes #2, Métier: Maçonnerie; Object Layer Attributes #2, NOI_UUID: d80b2029-7616-407a-9da1-afa361a85c10--1812; Object Layer Attributes #3, Unité: m²; Object Layer Attributes #3, Métier: Enduits et plâtrages; Object Layer Attributes #3, NOI_UUID: d80b2029-7616-407a-9da1-afa361a85c10--1811
 | r+1 | moellons 180 mm, briquettes 40 mm, enduit platre 10 mm | 5.7912 | 5.7912 |  | 10.0299 | 0.23 | 2.31648 | 2.5 | d80b2029-7616-407a-9da1-afa361a85c10--1311 | d80b2029-7616-407a-9da1-afa361a85c10--1463 | WallQuantities - GrossSideAreaRight: 25.2248 m2; GrossSideAreaLeft: 24.9748 m2; NetSideAreaRight: 25.2248 m2; NetSideAreaLeft: 24.9748 m2; Allplan Attributes - Object Layer Attributes #2, Unité: m²; Object Layer Attributes #2, Métier: Maçonnerie; Object Layer Attributes #2, NOI_UUID: d80b2029-7616-407a-9da1-afa361a85c10--1462; Object Layer Attributes #3, Unité: m²; Object Layer Attributes #3, Métier: Enduits et plâtrages; Object Layer Attributes #3, NOI_UUID: d80b2029-7616-407a-9da1-afa361a85c10--1461
 | r+1 | moellons 180 mm, briquettes 40 mm, enduit platre 10 mm | 5.7912 | 5.7912 |  | 10.0299 | 0.23 | 2.31648 | 2.5 | d80b2029-7616-407a-9da1-afa361a85c10--1322 | d80b2029-7616-407a-9da1-afa361a85c10--1465 | WallQuantities - GrossSideAreaRight: 25.2248 m2; GrossSideAreaLeft: 24.9748 m2; NetSideAreaRight: 25.2248 m2; NetSideAreaLeft: 24.9748 m2; Allplan Attributes - Object Layer Attributes #2, Unité: m²; Object Layer Attributes #2, Métier: Maçonnerie; Object Layer Attributes #2, NOI_UUID: d80b2029-7616-407a-9da1-afa361a85c10--1466; Object Layer Attributes #3, Unité: m²; Object Layer Attributes #3, Métier: Enduits et plâtrages; Object Layer Attributes #3, NOI_UUID: d80b2029-7616-407a-9da1-afa361a85c10--1467
 | r+1 | moellons 180 mm, briquettes 40 mm, enduit platre 10 mm | 11.2542 | 6.48175 |  | 18.9833 | 0.23 | 4.5017 | 2.5 | d80b2029-7616-407a-9da1-afa361a85c10--1324 | d80b2029-7616-407a-9da1-afa361a85c10--1795 | WallQuantities - GrossSideAreaRight: 49.625 m2; GrossSideAreaLeft: 46.275 m2; NetSideAreaRight: 28.875 m2; NetSideAreaLeft: 25.525 m2; Allplan Attributes - Object Layer Attributes #2, Unité: m²; Object Layer Attributes #2, Métier: Maçonnerie; Object Layer Attributes #2, NOI_UUID: d80b2029-7616-407a-9da1-afa361a85c10--1797; Object Layer Attributes #3, Unité: m²; Object Layer Attributes #3, Métier: Enduits et plâtrages; Object Layer Attributes #3, NOI_UUID: d80b2029-7616-407a-9da1-afa361a85c10--1796
 | r+1 | moellons 20.0776 mm | 0.0090349 | 0.0090349 | 0.0501939 | 0.02008 | 0.18 | 0.00361396 | 2.5 | d80b2029-7616-407a-9da1-afa361a85c10--1354 | d80b2029-7616-407a-9da1-afa361a85c10--1470
 | r+1 | moellons 20 mm | 0.009 | 0.009 | 0.05 | 0.02 | 0.18 | 0.0036 | 2.5 | d80b2029-7616-407a-9da1-afa361a85c10--1356 | d80b2029-7616-407a-9da1-afa361a85c10--1472
 | r+1 | moellons 20 mm | 0.009 | 0.009 | 0.05 | 0.02 | 0.18 | 0.0036 | 2.5 | d80b2029-7616-407a-9da1-afa361a85c10--1358 | d80b2029-7616-407a-9da1-afa361a85c10--1476
 | r+1 | moellons 20 mm | 0.009 | 0.009 | 0.05 | 0.02 | 0.18 | 0.0036 | 2.5 | d80b2029-7616-407a-9da1-afa361a85c10--1360 | d80b2029-7616-407a-9da1-afa361a85c10--1471
 | r+1 | moellons 20 mm | 0.009 | 0.009 | 0.05 | 0.02 | 0.18 | 0.0036 | 2.5 | d80b2029-7616-407a-9da1-afa361a85c10--1362 | d80b2029-7616-407a-9da1-afa361a85c10--1475
 | r+1 | moellons 20.1628 mm | 0.00907326 | 0.00907326 | 0.050407 | 0.02016 | 0.18 | 0.0036293 | 2.5 | d80b2029-7616-407a-9da1-afa361a85c10--1364 | d80b2029-7616-407a-9da1-afa361a85c10--1473
 | r+1 | moellons 20.1628 mm | 0.00907326 | 0.00907326 | 0.050407 | 0.02016 | 0.18 | 0.0036293 | 2.5 | d80b2029-7616-407a-9da1-afa361a85c10--1366 | d80b2029-7616-407a-9da1-afa361a85c10--1474
 | r+1 | moellons 180 mm | 4.5405 | 4.5405 | 25.225 | 10.09 | 0.18 | 1.8162 | 2.5 | d80b2029-7616-407a-9da1-afa361a85c10--1368 | d80b2029-7616-407a-9da1-afa361a85c10--1468
 | r+1 | moellons 180 mm | 4.5405 | 4.5405 | 25.225 | 10.09 | 0.18 | 1.8162 | 2.5 | d80b2029-7616-407a-9da1-afa361a85c10--1382 | d80b2029-7616-407a-9da1-afa361a85c10--1458
 | r+1 | moellons 180 mm | 4.5405 | 4.5405 | 25.225 | 10.09 | 0.18 | 1.8162 | 2.5 | d80b2029-7616-407a-9da1-afa361a85c10--1387 | d80b2029-7616-407a-9da1-afa361a85c10--1460
 | r+1 | moellons 180 mm | 4.5405 | 4.5405 | 25.225 | 10.09 | 0.18 | 1.8162 | 2.5 | d80b2029-7616-407a-9da1-afa361a85c10--1391 | d80b2029-7616-407a-9da1-afa361a85c10--1469
 | r+1 | moellons 180 mm | 4.5405 | 4.5405 | 25.225 | 10.09 | 0.18 | 1.8162 | 2.5 | d80b2029-7616-407a-9da1-afa361a85c10--1395 | d80b2029-7616-407a-9da1-afa361a85c10--1464
 | r+1 | moellons 180 mm | 4.5405 | 4.5405 | 25.225 | 10.09 | 0.18 | 1.8162 | 2.5 | d80b2029-7616-407a-9da1-afa361a85c10--1399 | d80b2029-7616-407a-9da1-afa361a85c10--1451
 | r+1 | moellons 180 mm | 4.5405 | 4.5405 | 25.225 | 10.09 | 0.18 | 1.8162 | 2.5 | d80b2029-7616-407a-9da1-afa361a85c10--1403 | d80b2029-7616-407a-9da1-afa361a85c10--1572
 | r+1 | moellons 180 mm | 4.5405 | 4.5405 | 25.225 | 10.09 | 0.18 | 1.8162 | 2.5 | d80b2029-7616-407a-9da1-afa361a85c10--1407 | d80b2029-7616-407a-9da1-afa361a85c10--1571
2 x  | r+1 | moellons 180 mm | 1.58402 | 1.58402 | 8.8001 | 3.52004 | 0.18 | 0.633607 | 2.5 | d80b2029-7616-407a-9da1-afa361a85c10--1411 | d80b2029-7616-407a-9da1-afa361a85c10--1449
 | r+1 | moellons 180 mm | 1.638 | 1.638 | 9.1 | 3.64 | 0.18 | 0.6552 | 2.5 | d80b2029-7616-407a-9da1-afa361a85c10--1412 | d80b2029-7616-407a-9da1-afa361a85c10--1457
2 x  | r+1 | moellons 180 mm | 1.58402 | 1.58402 | 8.8001 | 3.52004 | 0.18 | 0.633607 | 2.5 | d80b2029-7616-407a-9da1-afa361a85c10--1416 | d80b2029-7616-407a-9da1-afa361a85c10--1447
 | r+1 | moellons 180 mm | 1.638 | 1.638 | 9.1 | 3.64 | 0.18 | 0.6552 | 2.5 | d80b2029-7616-407a-9da1-afa361a85c10--1417 | d80b2029-7616-407a-9da1-afa361a85c10--1450
 | r+1 | moellons 180 mm | 2.9025 | 2.9025 | 16.125 | 6.45 | 0.18 | 1.161 | 2.5 | d80b2029-7616-407a-9da1-afa361a85c10--1423 | d80b2029-7616-407a-9da1-afa361a85c10--1459
 | r+1 | moellons 180 mm | 0.225 | 0.225 | 1.25 | 0.5 | 0.18 | 0.09 | 2.5 | d80b2029-7616-407a-9da1-afa361a85c10--1426 | d80b2029-7616-407a-9da1-afa361a85c10--1455
 | r+1 | moellons 180 mm | 1.4175 | 1.4175 | 7.875 | 3.15 | 0.18 | 0.567 | 2.5 | d80b2029-7616-407a-9da1-afa361a85c10--1428 | d80b2029-7616-407a-9da1-afa361a85c10--1448
 | r+1 | moellons 180 mm | 0.144 | 0.144 | 0.8 | 0.32 | 0.18 | 0.0576 | 2.5 | d80b2029-7616-407a-9da1-afa361a85c10--1430 | d80b2029-7616-407a-9da1-afa361a85c10--1456
 | r+1 | moellons 180 mm | 2.9025 | 2.9025 | 16.125 | 6.45 | 0.18 | 1.161 | 2.5 | d80b2029-7616-407a-9da1-afa361a85c10--1432 | d80b2029-7616-407a-9da1-afa361a85c10--1452
 | r+1 | moellons 180 mm | 0.225 | 0.225 | 1.25 | 0.5 | 0.18 | 0.09 | 2.5 | d80b2029-7616-407a-9da1-afa361a85c10--1434 | d80b2029-7616-407a-9da1-afa361a85c10--1453
 | r+1 | moellons 180 mm | 1.4175 | 1.4175 | 7.875 | 3.15 | 0.18 | 0.567 | 2.5 | d80b2029-7616-407a-9da1-afa361a85c10--1436 | d80b2029-7616-407a-9da1-afa361a85c10--1446
 | r+1 | moellons 180 mm | 0.144 | 0.144 | 0.8 | 0.32 | 0.18 | 0.0576 | 2.5 | d80b2029-7616-407a-9da1-afa361a85c10--1438 | d80b2029-7616-407a-9da1-afa361a85c10--1454
 | r+1 | moellons 180 mm, briquettes 40 mm, enduit platre 10 mm | 11.2542 | 6.48175 |  | 18.9833 | 0.23 | 4.5017 | 2.5 | d80b2029-7616-407a-9da1-afa361a85c10--1477 | d80b2029-7616-407a-9da1-afa361a85c10--1827 | WallQuantities - GrossSideAreaRight: 49.625 m2; GrossSideAreaLeft: 46.275 m2; NetSideAreaRight: 28.875 m2; NetSideAreaLeft: 25.525 m2; Allplan Attributes - Object Layer Attributes #2, Unité: m²; Object Layer Attributes #2, Métier: Maçonnerie; Object Layer Attributes #2, NOI_UUID: d80b2029-7616-407a-9da1-afa361a85c10--1826; Object Layer Attributes #3, Unité: m²; Object Layer Attributes #3, Métier: Enduits et plâtrages; Object Layer Attributes #3, NOI_UUID: d80b2029-7616-407a-9da1-afa361a85c10--1825
 | r+1 | moellons 20.0776 mm | 0.0090349 | 0.0090349 | 0.0501939 | 0.02008 | 0.18 | 0.00361396 | 2.5 | d80b2029-7616-407a-9da1-afa361a85c10--1479 | d80b2029-7616-407a-9da1-afa361a85c10--1675
 | r+1 | moellons 20 mm | 0.009 | 0.009 | 0.05 | 0.02 | 0.18 | 0.0036 | 2.5 | d80b2029-7616-407a-9da1-afa361a85c10--1481 | d80b2029-7616-407a-9da1-afa361a85c10--1536
 | r+1 | moellons 20.1628 mm | 0.00907326 | 0.00907326 | 0.050407 | 0.02016 | 0.18 | 0.0036293 | 2.5 | d80b2029-7616-407a-9da1-afa361a85c10--1483 | d80b2029-7616-407a-9da1-afa361a85c10--1592
 | r+1 | moellons 180 mm | 4.5405 | 4.5405 | 25.225 | 10.09 | 0.18 | 1.8162 | 2.5 | d80b2029-7616-407a-9da1-afa361a85c10--1485 | d80b2029-7616-407a-9da1-afa361a85c10--1676
 | r+1 | moellons 180 mm | 4.5405 | 4.5405 | 25.225 | 10.09 | 0.18 | 1.8162 | 2.5 | d80b2029-7616-407a-9da1-afa361a85c10--1494 | d80b2029-7616-407a-9da1-afa361a85c10--1677
 | r+1 | moellons 180 mm | 4.54046 | 4.54046 | 25.2248 | 10.0899 | 0.18 | 1.81618 | 2.5 | d80b2029-7616-407a-9da1-afa361a85c10--1496 | d80b2029-7616-407a-9da1-afa361a85c10--1591
 | r+1 | moellons 180 mm | 4.54046 | 4.54046 | 25.2248 | 10.0899 | 0.18 | 1.81618 | 2.5 | d80b2029-7616-407a-9da1-afa361a85c10--1498 | d80b2029-7616-407a-9da1-afa361a85c10--1593
2 x  | r+1 | moellons 180 mm | 1.58402 | 1.58402 | 8.8001 | 3.52004 | 0.18 | 0.633607 | 2.5 | d80b2029-7616-407a-9da1-afa361a85c10--1500 | d80b2029-7616-407a-9da1-afa361a85c10--1533
 | r+1 | moellons 180 mm | 1.638 | 1.638 | 9.1 | 3.64 | 0.18 | 0.6552 | 2.5 | d80b2029-7616-407a-9da1-afa361a85c10--1501 | d80b2029-7616-407a-9da1-afa361a85c10--1529
 | r+1 | moellons 180 mm | 2.9025 | 2.9025 | 16.125 | 6.45 | 0.18 | 1.161 | 2.5 | d80b2029-7616-407a-9da1-afa361a85c10--1505 | d80b2029-7616-407a-9da1-afa361a85c10--1528
 | r+1 | moellons 180 mm | 0.225 | 0.225 | 1.25 | 0.5 | 0.18 | 0.09 | 2.5 | d80b2029-7616-407a-9da1-afa361a85c10--1507 | d80b2029-7616-407a-9da1-afa361a85c10--1531
 | r+1 | moellons 180 mm | 1.4175 | 1.4175 | 7.875 | 3.15 | 0.18 | 0.567 | 2.5 | d80b2029-7616-407a-9da1-afa361a85c10--1509 | d80b2029-7616-407a-9da1-afa361a85c10--1534
 | r+1 | moellons 180 mm | 0.144 | 0.144 | 0.8 | 0.32 | 0.18 | 0.0576 | 2.5 | d80b2029-7616-407a-9da1-afa361a85c10--1511 | d80b2029-7616-407a-9da1-afa361a85c10--1530
 | r+1 | moellons 180 mm, briquettes 40 mm, enduit platre 10 mm | 5.79125 | 5.64267 |  | 10.03 | 0.23 | 2.3165 | 2.5 | d80b2029-7616-407a-9da1-afa361a85c10--1595 | d80b2029-7616-407a-9da1-afa361a85c10--1887 | WallQuantities - GrossSideAreaRight: 25.225 m2; GrossSideAreaLeft: 24.975 m2; NetSideAreaRight: 24.579 m2; NetSideAreaLeft: 24.329 m2; Allplan Attributes - Object Layer Attributes #2, Unité: m²; Object Layer Attributes #2, Métier: Maçonnerie; Object Layer Attributes #2, NOI_UUID: d80b2029-7616-407a-9da1-afa361a85c10--1886; Object Layer Attributes #3, Unité: m²; Object Layer Attributes #3, Métier: Enduits et plâtrages; Object Layer Attributes #3, NOI_UUID: d80b2029-7616-407a-9da1-afa361a85c10--1885
 | r+1 | moellons 179.996 mm, briquettes 40 mm, enduit platre 10 mm | 7.9761 | 6.0717 |  | 13.3633 | 0.23 | 3.19044 | 2.5 | d80b2029-7616-407a-9da1-afa361a85c10--1596 | d80b2029-7616-407a-9da1-afa361a85c10--1702 | WallQuantities - GrossSideAreaRight: 35.275 m2; GrossSideAreaLeft: 32.375 m2; NetSideAreaRight: 26.995 m2; NetSideAreaLeft: 24.095 m2; Allplan Attributes - Object Layer Attributes #2, Unité: m²; Object Layer Attributes #2, Métier: Maçonnerie; Object Layer Attributes #2, NOI_UUID: d80b2029-7616-407a-9da1-afa361a85c10--1703; Object Layer Attributes #3, Unité: m²; Object Layer Attributes #3, Métier: Enduits et plâtrages; Object Layer Attributes #3, NOI_UUID: d80b2029-7616-407a-9da1-afa361a85c10--1704
 | r+1 | moellons 180 mm, briquettes 40 mm, enduit platre 10 mm | 5.7912 | 5.16652 |  | 10.0299 | 0.23 | 2.31648 | 2.5 | d80b2029-7616-407a-9da1-afa361a85c10--1629 | d80b2029-7616-407a-9da1-afa361a85c10--1878 | WallQuantities - GrossSideAreaRight: 25.2248 m2; GrossSideAreaLeft: 24.9748 m2; NetSideAreaRight: 22.5088 m2; NetSideAreaLeft: 22.2588 m2; Allplan Attributes - Object Layer Attributes #2, Unité: m²; Object Layer Attributes #2, Métier: Maçonnerie; Object Layer Attributes #2, NOI_UUID: d80b2029-7616-407a-9da1-afa361a85c10--1877; Object Layer Attributes #3, Unité: m²; Object Layer Attributes #3, Métier: Enduits et plâtrages; Object Layer Attributes #3, NOI_UUID: d80b2029-7616-407a-9da1-afa361a85c10--1876
 | r+1 | moellons 180 mm, briquettes 40 mm, enduit platre 10 mm | 5.79125 | 5.69741 |  | 10.03 | 0.23 | 2.3165 | 2.5 | d80b2029-7616-407a-9da1-afa361a85c10--1630 | d80b2029-7616-407a-9da1-afa361a85c10--1842 | WallQuantities - GrossSideAreaRight: 25.225 m2; GrossSideAreaLeft: 24.975 m2; NetSideAreaRight: 24.817 m2; NetSideAreaLeft: 24.567 m2; Allplan Attributes - Object Layer Attributes #2, Unité: m²; Object Layer Attributes #2, Métier: Maçonnerie; Object Layer Attributes #2, NOI_UUID: d80b2029-7616-407a-9da1-afa361a85c10--1840; Object Layer Attributes #3, Unité: m²; Object Layer Attributes #3, Métier: Enduits et plâtrages; Object Layer Attributes #3, NOI_UUID: d80b2029-7616-407a-9da1-afa361a85c10--1841
 | r+1 | moellons 180 mm, briquettes 40 mm, enduit platre 10 mm | 4.05712 | 3.10492 |  | 6.80167 | 0.23 | 1.62285 | 2.5 | d80b2029-7616-407a-9da1-afa361a85c10--1643 | d80b2029-7616-407a-9da1-afa361a85c10--1584 | WallQuantities - GrossSideAreaRight: 17.9375 m2; GrossSideAreaLeft: 16.4875 m2; NetSideAreaRight: 13.7975 m2; NetSideAreaLeft: 12.3475 m2; Allplan Attributes - Object Layer Attributes #2, Unité: m²; Object Layer Attributes #2, Métier: Maçonnerie; Object Layer Attributes #2, NOI_UUID: d80b2029-7616-407a-9da1-afa361a85c10--1586; Object Layer Attributes #3, Unité: m²; Object Layer Attributes #3, Métier: Enduits et plâtrages; Object Layer Attributes #3, NOI_UUID: d80b2029-7616-407a-9da1-afa361a85c10--1585; Object Layer Attributes #1, Matériau: moellons
 | r+1 | moellons 180 mm, briquettes 40 mm, enduit platre 10 mm | 3.98812 | 3.51202 |  | 6.68167 | 0.23 | 1.59525 | 2.5 | d80b2029-7616-407a-9da1-afa361a85c10--1651 | d80b2029-7616-407a-9da1-afa361a85c10--1695 | WallQuantities - GrossSideAreaRight: 17.6375 m2; GrossSideAreaLeft: 16.1875 m2; NetSideAreaRight: 15.5675 m2; NetSideAreaLeft: 14.1175 m2; Allplan Attributes - Object Layer Attributes #2, Unité: m²; Object Layer Attributes #2, Métier: Maçonnerie; Object Layer Attributes #2, NOI_UUID: d80b2029-7616-407a-9da1-afa361a85c10--1694; Object Layer Attributes #3, Unité: m²; Object Layer Attributes #3, Métier: Enduits et plâtrages; Object Layer Attributes #3, NOI_UUID: d80b2029-7616-407a-9da1-afa361a85c10--1693; Object Layer Attributes #1, Matériau: moellons
 | r+1 | moellons 180 mm, briquettes 40 mm, enduit platre 10 mm | 4.05713 | 3.10493 |  | 6.80167 | 0.23 | 1.62285 | 2.5 | d80b2029-7616-407a-9da1-afa361a85c10--1662 | d80b2029-7616-407a-9da1-afa361a85c10--1684 | WallQuantities - GrossSideAreaRight: 17.9375 m2; GrossSideAreaLeft: 16.4875 m2; NetSideAreaRight: 13.7975 m2; NetSideAreaLeft: 12.3475 m2; Allplan Attributes - Object Layer Attributes #2, Unité: m²; Object Layer Attributes #2, Métier: Maçonnerie; Object Layer Attributes #2, NOI_UUID: d80b2029-7616-407a-9da1-afa361a85c10--1685; Object Layer Attributes #3, Unité: m²; Object Layer Attributes #3, Métier: Enduits et plâtrages; Object Layer Attributes #3, NOI_UUID: d80b2029-7616-407a-9da1-afa361a85c10--1686
 | r+1 | moellons 180 mm, briquettes 40 mm, enduit platre 10 mm | 4.05713 | 3.10493 |  | 6.80167 | 0.23 | 1.62285 | 2.5 | d80b2029-7616-407a-9da1-afa361a85c10--1594 | d80b2029-7616-407a-9da1-afa361a85c10--1548 | WallQuantities - GrossSideAreaRight: 17.9375 m2; GrossSideAreaLeft: 16.4875 m2; NetSideAreaRight: 13.7975 m2; NetSideAreaLeft: 12.3475 m2; Allplan Attributes - Object Layer Attributes #2, Unité: m²; Object Layer Attributes #2, Métier: Maçonnerie; Object Layer Attributes #2, NOI_UUID: d80b2029-7616-407a-9da1-afa361a85c10--1549; Object Layer Attributes #3, Unité: m²; Object Layer Attributes #3, Métier: Enduits et plâtrages; Object Layer Attributes #3, NOI_UUID: d80b2029-7616-407a-9da1-afa361a85c10--1550; Object Layer Attributes #1, Matériau: moellons
 | r+2 | moellons 180 mm, briquettes 40 mm, enduit platre 10 mm | 5.8765 | 5.78266 |  | 10.1067 | 0.23 | 2.3506 | 2.5 | 25afd9b5-9bbd-43b9-8fed-22435f7cc0c3--773 | 25afd9b5-9bbd-43b9-8fed-22435f7cc0c3--1318 | WallQuantities - GrossSideAreaRight: 25.675 m2; GrossSideAreaLeft: 25 m2; NetSideAreaRight: 25.267 m2; NetSideAreaLeft: 24.592 m2; Allplan Attributes - Object Layer Attributes #2, Unité: m²; Object Layer Attributes #2, Métier: Maçonnerie; Object Layer Attributes #2, NOI_UUID: 25afd9b5-9bbd-43b9-8fed-22435f7cc0c3--1320; Object Layer Attributes #3, Unité: m²; Object Layer Attributes #3, Métier: Enduits et plâtrages; Object Layer Attributes #3, NOI_UUID: 25afd9b5-9bbd-43b9-8fed-22435f7cc0c3--1319
 | r+2 | moellons 180 mm, briquettes 40 mm, enduit platre 10 mm | 11.169 | 6.3965 |  | 18.9067 | 0.23 | 4.4676 | 2.5 | 25afd9b5-9bbd-43b9-8fed-22435f7cc0c3--775 | 25afd9b5-9bbd-43b9-8fed-22435f7cc0c3--1309 | WallQuantities - GrossSideAreaRight: 49.175 m2; GrossSideAreaLeft: 46.25 m2; NetSideAreaRight: 28.425 m2; NetSideAreaLeft: 25.5 m2; Allplan Attributes - Object Layer Attributes #2, Unité: m²; Object Layer Attributes #2, Métier: Maçonnerie; Object Layer Attributes #2, NOI_UUID: 25afd9b5-9bbd-43b9-8fed-22435f7cc0c3--1311; Object Layer Attributes #3, Unité: m²; Object Layer Attributes #3, Métier: Enduits et plâtrages; Object Layer Attributes #3, NOI_UUID: 25afd9b5-9bbd-43b9-8fed-22435f7cc0c3--1310
 | r+2 | moellons 180 mm, briquettes 40 mm, enduit platre 10 mm | 5.7912 | 5.7912 |  | 10.0299 | 0.23 | 2.31648 | 2.5 | 25afd9b5-9bbd-43b9-8fed-22435f7cc0c3--783 | 25afd9b5-9bbd-43b9-8fed-22435f7cc0c3--1267 | WallQuantities - GrossSideAreaRight: 25.2248 m2; GrossSideAreaLeft: 24.9748 m2; NetSideAreaRight: 25.2248 m2; NetSideAreaLeft: 24.9748 m2; Allplan Attributes - Object Layer Attributes #2, Unité: m²; Object Layer Attributes #2, Métier: Maçonnerie; Object Layer Attributes #2, NOI_UUID: 25afd9b5-9bbd-43b9-8fed-22435f7cc0c3--1266; Object Layer Attributes #3, Unité: m²; Object Layer Attributes #3, Métier: Enduits et plâtrages; Object Layer Attributes #3, NOI_UUID: 25afd9b5-9bbd-43b9-8fed-22435f7cc0c3--1265
 | r+2 | moellons 180 mm, briquettes 40 mm, enduit platre 10 mm | 5.7912 | 5.7912 |  | 10.0299 | 0.23 | 2.31648 | 2.5 | 25afd9b5-9bbd-43b9-8fed-22435f7cc0c3--794 | 25afd9b5-9bbd-43b9-8fed-22435f7cc0c3--1269 | WallQuantities - GrossSideAreaRight: 25.2248 m2; GrossSideAreaLeft: 24.9748 m2; NetSideAreaRight: 25.2248 m2; NetSideAreaLeft: 24.9748 m2; Allplan Attributes - Object Layer Attributes #2, Unité: m²; Object Layer Attributes #2, Métier: Maçonnerie; Object Layer Attributes #2, NOI_UUID: 25afd9b5-9bbd-43b9-8fed-22435f7cc0c3--1270; Object Layer Attributes #3, Unité: m²; Object Layer Attributes #3, Métier: Enduits et plâtrages; Object Layer Attributes #3, NOI_UUID: 25afd9b5-9bbd-43b9-8fed-22435f7cc0c3--1271
 | r+2 | moellons 180 mm, briquettes 40 mm, enduit platre 10 mm | 11.2542 | 6.48175 |  | 18.9833 | 0.23 | 4.5017 | 2.5 | 25afd9b5-9bbd-43b9-8fed-22435f7cc0c3--796 | 25afd9b5-9bbd-43b9-8fed-22435f7cc0c3--1306 | WallQuantities - GrossSideAreaRight: 49.625 m2; GrossSideAreaLeft: 46.275 m2; NetSideAreaRight: 28.875 m2; NetSideAreaLeft: 25.525 m2; Allplan Attributes - Object Layer Attributes #2, Unité: m²; Object Layer Attributes #2, Métier: Maçonnerie; Object Layer Attributes #2, NOI_UUID: 25afd9b5-9bbd-43b9-8fed-22435f7cc0c3--1308; Object Layer Attributes #3, Unité: m²; Object Layer Attributes #3, Métier: Enduits et plâtrages; Object Layer Attributes #3, NOI_UUID: 25afd9b5-9bbd-43b9-8fed-22435f7cc0c3--1307
 | r+2 | moellons 20.0776 mm | 0.0090349 | 0.0090349 | 0.0501939 | 0.02008 | 0.18 | 0.00361396 | 2.5 | 25afd9b5-9bbd-43b9-8fed-22435f7cc0c3--826 | 25afd9b5-9bbd-43b9-8fed-22435f7cc0c3--1245
 | r+2 | moellons 20 mm | 0.009 | 0.009 | 0.05 | 0.02 | 0.18 | 0.0036 | 2.5 | 25afd9b5-9bbd-43b9-8fed-22435f7cc0c3--828 | 25afd9b5-9bbd-43b9-8fed-22435f7cc0c3--1274
 | r+2 | moellons 20 mm | 0.009 | 0.009 | 0.05 | 0.02 | 0.18 | 0.0036 | 2.5 | 25afd9b5-9bbd-43b9-8fed-22435f7cc0c3--830 | 25afd9b5-9bbd-43b9-8fed-22435f7cc0c3--1278
 | r+2 | moellons 20 mm | 0.009 | 0.009 | 0.05 | 0.02 | 0.18 | 0.0036 | 2.5 | 25afd9b5-9bbd-43b9-8fed-22435f7cc0c3--832 | 25afd9b5-9bbd-43b9-8fed-22435f7cc0c3--1273
 | r+2 | moellons 20 mm | 0.009 | 0.009 | 0.05 | 0.02 | 0.18 | 0.0036 | 2.5 | 25afd9b5-9bbd-43b9-8fed-22435f7cc0c3--834 | 25afd9b5-9bbd-43b9-8fed-22435f7cc0c3--1277
 | r+2 | moellons 20.1628 mm | 0.00907326 | 0.00907326 | 0.050407 | 0.02016 | 0.18 | 0.0036293 | 2.5 | 25afd9b5-9bbd-43b9-8fed-22435f7cc0c3--836 | 25afd9b5-9bbd-43b9-8fed-22435f7cc0c3--1275
 | r+2 | moellons 20.1628 mm | 0.00907326 | 0.00907326 | 0.050407 | 0.02016 | 0.18 | 0.0036293 | 2.5 | 25afd9b5-9bbd-43b9-8fed-22435f7cc0c3--838 | 25afd9b5-9bbd-43b9-8fed-22435f7cc0c3--1276
 | r+2 | moellons 180 mm | 4.5405 | 4.5405 | 25.225 | 10.09 | 0.18 | 1.8162 | 2.5 | 25afd9b5-9bbd-43b9-8fed-22435f7cc0c3--840 | 25afd9b5-9bbd-43b9-8fed-22435f7cc0c3--1246
 | r+2 | moellons 180 mm | 4.5405 | 4.5405 | 25.225 | 10.09 | 0.18 | 1.8162 | 2.5 | 25afd9b5-9bbd-43b9-8fed-22435f7cc0c3--854 | 25afd9b5-9bbd-43b9-8fed-22435f7cc0c3--1247
 | r+2 | moellons 180 mm | 4.5405 | 4.5405 | 25.225 | 10.09 | 0.18 | 1.8162 | 2.5 | 25afd9b5-9bbd-43b9-8fed-22435f7cc0c3--858 | 25afd9b5-9bbd-43b9-8fed-22435f7cc0c3--1264
 | r+2 | moellons 180 mm | 4.5405 | 4.5405 | 25.225 | 10.09 | 0.18 | 1.8162 | 2.5 | 25afd9b5-9bbd-43b9-8fed-22435f7cc0c3--862 | 25afd9b5-9bbd-43b9-8fed-22435f7cc0c3--1272
 | r+2 | moellons 180 mm | 4.5405 | 4.5405 | 25.225 | 10.09 | 0.18 | 1.8162 | 2.5 | 25afd9b5-9bbd-43b9-8fed-22435f7cc0c3--866 | 25afd9b5-9bbd-43b9-8fed-22435f7cc0c3--1268
 | r+2 | moellons 180 mm | 4.5405 | 4.5405 | 25.225 | 10.09 | 0.18 | 1.8162 | 2.5 | 25afd9b5-9bbd-43b9-8fed-22435f7cc0c3--870 | 25afd9b5-9bbd-43b9-8fed-22435f7cc0c3--1256
 | r+2 | moellons 180 mm | 4.5405 | 4.5405 | 25.225 | 10.09 | 0.18 | 1.8162 | 2.5 | 25afd9b5-9bbd-43b9-8fed-22435f7cc0c3--874 | 25afd9b5-9bbd-43b9-8fed-22435f7cc0c3--1287
 | r+2 | moellons 180 mm | 4.5405 | 4.5405 | 25.225 | 10.09 | 0.18 | 1.8162 | 2.5 | 25afd9b5-9bbd-43b9-8fed-22435f7cc0c3--878 | 25afd9b5-9bbd-43b9-8fed-22435f7cc0c3--1286
2 x  | r+2 | moellons 180 mm | 1.58402 | 1.58402 | 8.8001 | 3.52004 | 0.18 | 0.633607 | 2.5 | 25afd9b5-9bbd-43b9-8fed-22435f7cc0c3--882 | 25afd9b5-9bbd-43b9-8fed-22435f7cc0c3--1254
 | r+2 | moellons 180 mm | 1.638 | 1.638 | 9.1 | 3.64 | 0.18 | 0.6552 | 2.5 | 25afd9b5-9bbd-43b9-8fed-22435f7cc0c3--883 | 25afd9b5-9bbd-43b9-8fed-22435f7cc0c3--1262
2 x  | r+2 | moellons 180 mm | 1.58402 | 1.58402 | 8.8001 | 3.52004 | 0.18 | 0.633607 | 2.5 | 25afd9b5-9bbd-43b9-8fed-22435f7cc0c3--887 | 25afd9b5-9bbd-43b9-8fed-22435f7cc0c3--1252
 | r+2 | moellons 180 mm | 1.638 | 1.638 | 9.1 | 3.64 | 0.18 | 0.6552 | 2.5 | 25afd9b5-9bbd-43b9-8fed-22435f7cc0c3--888 | 25afd9b5-9bbd-43b9-8fed-22435f7cc0c3--1255
 | r+2 | moellons 180 mm | 2.9025 | 2.9025 | 16.125 | 6.45 | 0.18 | 1.161 | 2.5 | 25afd9b5-9bbd-43b9-8fed-22435f7cc0c3--894 | 25afd9b5-9bbd-43b9-8fed-22435f7cc0c3--1263
 | r+2 | moellons 180 mm | 0.225 | 0.225 | 1.25 | 0.5 | 0.18 | 0.09 | 2.5 | 25afd9b5-9bbd-43b9-8fed-22435f7cc0c3--897 | 25afd9b5-9bbd-43b9-8fed-22435f7cc0c3--1260
 | r+2 | moellons 180 mm | 1.4175 | 1.4175 | 7.875 | 3.15 | 0.18 | 0.567 | 2.5 | 25afd9b5-9bbd-43b9-8fed-22435f7cc0c3--899 | 25afd9b5-9bbd-43b9-8fed-22435f7cc0c3--1253
 | r+2 | moellons 180 mm | 0.144 | 0.144 | 0.8 | 0.32 | 0.18 | 0.0576 | 2.5 | 25afd9b5-9bbd-43b9-8fed-22435f7cc0c3--901 | 25afd9b5-9bbd-43b9-8fed-22435f7cc0c3--1261
 | r+2 | moellons 180 mm | 2.9025 | 2.9025 | 16.125 | 6.45 | 0.18 | 1.161 | 2.5 | 25afd9b5-9bbd-43b9-8fed-22435f7cc0c3--903 | 25afd9b5-9bbd-43b9-8fed-22435f7cc0c3--1257
 | r+2 | moellons 180 mm | 0.225 | 0.225 | 1.25 | 0.5 | 0.18 | 0.09 | 2.5 | 25afd9b5-9bbd-43b9-8fed-22435f7cc0c3--905 | 25afd9b5-9bbd-43b9-8fed-22435f7cc0c3--1258
 | r+2 | moellons 180 mm | 1.4175 | 1.4175 | 7.875 | 3.15 | 0.18 | 0.567 | 2.5 | 25afd9b5-9bbd-43b9-8fed-22435f7cc0c3--907 | 25afd9b5-9bbd-43b9-8fed-22435f7cc0c3--1251
 | r+2 | moellons 180 mm | 0.144 | 0.144 | 0.8 | 0.32 | 0.18 | 0.0576 | 2.5 | 25afd9b5-9bbd-43b9-8fed-22435f7cc0c3--909 | 25afd9b5-9bbd-43b9-8fed-22435f7cc0c3--1259
 | r+2 | moellons 180 mm, briquettes 40 mm, enduit platre 10 mm | 11.2542 | 6.48175 |  | 18.9833 | 0.23 | 4.5017 | 2.5 | 25afd9b5-9bbd-43b9-8fed-22435f7cc0c3--916 | 25afd9b5-9bbd-43b9-8fed-22435f7cc0c3--1314 | WallQuantities - GrossSideAreaRight: 49.625 m2; GrossSideAreaLeft: 46.275 m2; NetSideAreaRight: 28.875 m2; NetSideAreaLeft: 25.525 m2; Allplan Attributes - Object Layer Attributes #2, Unité: m²; Object Layer Attributes #2, Métier: Maçonnerie; Object Layer Attributes #2, NOI_UUID: 25afd9b5-9bbd-43b9-8fed-22435f7cc0c3--1313; Object Layer Attributes #3, Unité: m²; Object Layer Attributes #3, Métier: Enduits et plâtrages; Object Layer Attributes #3, NOI_UUID: 25afd9b5-9bbd-43b9-8fed-22435f7cc0c3--1312
 | r+2 | moellons 20.0776 mm | 0.0090349 | 0.0090349 | 0.0501939 | 0.02008 | 0.18 | 0.00361396 | 2.5 | 25afd9b5-9bbd-43b9-8fed-22435f7cc0c3--918 | 25afd9b5-9bbd-43b9-8fed-22435f7cc0c3--1294
 | r+2 | moellons 20 mm | 0.009 | 0.009 | 0.05 | 0.02 | 0.18 | 0.0036 | 2.5 | 25afd9b5-9bbd-43b9-8fed-22435f7cc0c3--920 | 25afd9b5-9bbd-43b9-8fed-22435f7cc0c3--1285
 | r+2 | moellons 20.1628 mm | 0.00907326 | 0.00907326 | 0.050407 | 0.02016 | 0.18 | 0.0036293 | 2.5 | 25afd9b5-9bbd-43b9-8fed-22435f7cc0c3--922 | 25afd9b5-9bbd-43b9-8fed-22435f7cc0c3--1292
 | r+2 | moellons 180 mm | 4.5405 | 4.5405 | 25.225 | 10.09 | 0.18 | 1.8162 | 2.5 | 25afd9b5-9bbd-43b9-8fed-22435f7cc0c3--924 | 25afd9b5-9bbd-43b9-8fed-22435f7cc0c3--1295
 | r+2 | moellons 180 mm | 4.5405 | 4.5405 | 25.225 | 10.09 | 0.18 | 1.8162 | 2.5 | 25afd9b5-9bbd-43b9-8fed-22435f7cc0c3--933 | 25afd9b5-9bbd-43b9-8fed-22435f7cc0c3--1296
 | r+2 | moellons 180 mm | 4.54046 | 4.54046 | 25.2248 | 10.0899 | 0.18 | 1.81618 | 2.5 | 25afd9b5-9bbd-43b9-8fed-22435f7cc0c3--935 | 25afd9b5-9bbd-43b9-8fed-22435f7cc0c3--1291
 | r+2 | moellons 180 mm | 4.54046 | 4.54046 | 25.2248 | 10.0899 | 0.18 | 1.81618 | 2.5 | 25afd9b5-9bbd-43b9-8fed-22435f7cc0c3--937 | 25afd9b5-9bbd-43b9-8fed-22435f7cc0c3--1293
2 x  | r+2 | moellons 180 mm | 1.58402 | 1.58402 | 8.8001 | 3.52004 | 0.18 | 0.633607 | 2.5 | 25afd9b5-9bbd-43b9-8fed-22435f7cc0c3--939 | 25afd9b5-9bbd-43b9-8fed-22435f7cc0c3--1283
 | r+2 | moellons 180 mm | 1.638 | 1.638 | 9.1 | 3.64 | 0.18 | 0.6552 | 2.5 | 25afd9b5-9bbd-43b9-8fed-22435f7cc0c3--940 | 25afd9b5-9bbd-43b9-8fed-22435f7cc0c3--1280
 | r+2 | moellons 180 mm | 2.9025 | 2.9025 | 16.125 | 6.45 | 0.18 | 1.161 | 2.5 | 25afd9b5-9bbd-43b9-8fed-22435f7cc0c3--944 | 25afd9b5-9bbd-43b9-8fed-22435f7cc0c3--1279
 | r+2 | moellons 180 mm | 0.225 | 0.225 | 1.25 | 0.5 | 0.18 | 0.09 | 2.5 | 25afd9b5-9bbd-43b9-8fed-22435f7cc0c3--946 | 25afd9b5-9bbd-43b9-8fed-22435f7cc0c3--1282
 | r+2 | moellons 180 mm | 1.4175 | 1.4175 | 7.875 | 3.15 | 0.18 | 0.567 | 2.5 | 25afd9b5-9bbd-43b9-8fed-22435f7cc0c3--948 | 25afd9b5-9bbd-43b9-8fed-22435f7cc0c3--1284
 | r+2 | moellons 180 mm | 0.144 | 0.144 | 0.8 | 0.32 | 0.18 | 0.0576 | 2.5 | 25afd9b5-9bbd-43b9-8fed-22435f7cc0c3--950 | 25afd9b5-9bbd-43b9-8fed-22435f7cc0c3--1281
 | r+2 | moellons 180 mm, briquettes 40 mm, enduit platre 10 mm | 5.79125 | 5.64267 |  | 10.03 | 0.23 | 2.3165 | 2.5 | 25afd9b5-9bbd-43b9-8fed-22435f7cc0c3--978 | 25afd9b5-9bbd-43b9-8fed-22435f7cc0c3--1242 | WallQuantities - GrossSideAreaRight: 25.225 m2; GrossSideAreaLeft: 24.975 m2; NetSideAreaRight: 24.579 m2; NetSideAreaLeft: 24.329 m2; Allplan Attributes - Object Layer Attributes #2, Unité: m²; Object Layer Attributes #2, Métier: Maçonnerie; Object Layer Attributes #2, NOI_UUID: 25afd9b5-9bbd-43b9-8fed-22435f7cc0c3--1243; Object Layer Attributes #3, Unité: m²; Object Layer Attributes #3, Métier: Enduits et plâtrages; Object Layer Attributes #3, NOI_UUID: 25afd9b5-9bbd-43b9-8fed-22435f7cc0c3--1244
 | r+2 | moellons 179.996 mm, briquettes 40 mm, enduit platre 10 mm | 7.9761 | 6.0717 |  | 13.3633 | 0.23 | 3.19044 | 2.5 | 25afd9b5-9bbd-43b9-8fed-22435f7cc0c3--979 | 25afd9b5-9bbd-43b9-8fed-22435f7cc0c3--1303 | WallQuantities - GrossSideAreaRight: 35.275 m2; GrossSideAreaLeft: 32.375 m2; NetSideAreaRight: 26.995 m2; NetSideAreaLeft: 24.095 m2; Allplan Attributes - Object Layer Attributes #2, Unité: m²; Object Layer Attributes #2, Métier: Maçonnerie; Object Layer Attributes #2, NOI_UUID: 25afd9b5-9bbd-43b9-8fed-22435f7cc0c3--1304; Object Layer Attributes #3, Unité: m²; Object Layer Attributes #3, Métier: Enduits et plâtrages; Object Layer Attributes #3, NOI_UUID: 25afd9b5-9bbd-43b9-8fed-22435f7cc0c3--1305
 | r+2 | moellons 180 mm, briquettes 40 mm, enduit platre 10 mm | 5.7912 | 5.16652 |  | 10.0299 | 0.23 | 2.31648 | 2.5 | 25afd9b5-9bbd-43b9-8fed-22435f7cc0c3--1004 | 25afd9b5-9bbd-43b9-8fed-22435f7cc0c3--1323 | WallQuantities - GrossSideAreaRight: 25.2248 m2; GrossSideAreaLeft: 24.9748 m2; NetSideAreaRight: 22.5088 m2; NetSideAreaLeft: 22.2588 m2; Allplan Attributes - Object Layer Attributes #2, Unité: m²; Object Layer Attributes #2, Métier: Maçonnerie; Object Layer Attributes #2, NOI_UUID: 25afd9b5-9bbd-43b9-8fed-22435f7cc0c3--1322; Object Layer Attributes #3, Unité: m²; Object Layer Attributes #3, Métier: Enduits et plâtrages; Object Layer Attributes #3, NOI_UUID: 25afd9b5-9bbd-43b9-8fed-22435f7cc0c3--1321
 | r+2 | moellons 180 mm, briquettes 40 mm, enduit platre 10 mm | 5.79125 | 5.69741 |  | 10.03 | 0.23 | 2.3165 | 2.5 | 25afd9b5-9bbd-43b9-8fed-22435f7cc0c3--1005 | 25afd9b5-9bbd-43b9-8fed-22435f7cc0c3--1317 | WallQuantities - GrossSideAreaRight: 25.225 m2; GrossSideAreaLeft: 24.975 m2; NetSideAreaRight: 24.817 m2; NetSideAreaLeft: 24.567 m2; Allplan Attributes - Object Layer Attributes #2, Unité: m²; Object Layer Attributes #2, Métier: Maçonnerie; Object Layer Attributes #2, NOI_UUID: 25afd9b5-9bbd-43b9-8fed-22435f7cc0c3--1315; Object Layer Attributes #3, Unité: m²; Object Layer Attributes #3, Métier: Enduits et plâtrages; Object Layer Attributes #3, NOI_UUID: 25afd9b5-9bbd-43b9-8fed-22435f7cc0c3--1316
 | r+2 | moellons 180 mm, briquettes 40 mm, enduit platre 10 mm | 4.05712 | 3.10492 |  | 6.80167 | 0.23 | 1.62285 | 2.5 | 25afd9b5-9bbd-43b9-8fed-22435f7cc0c3--1018 | 25afd9b5-9bbd-43b9-8fed-22435f7cc0c3--1288 | WallQuantities - GrossSideAreaRight: 17.9375 m2; GrossSideAreaLeft: 16.4875 m2; NetSideAreaRight: 13.7975 m2; NetSideAreaLeft: 12.3475 m2; Allplan Attributes - Object Layer Attributes #2, Unité: m²; Object Layer Attributes #2, Métier: Maçonnerie; Object Layer Attributes #2, NOI_UUID: 25afd9b5-9bbd-43b9-8fed-22435f7cc0c3--1290; Object Layer Attributes #3, Unité: m²; Object Layer Attributes #3, Métier: Enduits et plâtrages; Object Layer Attributes #3, NOI_UUID: 25afd9b5-9bbd-43b9-8fed-22435f7cc0c3--1289; Object Layer Attributes #1, Matériau: moellons
 | r+2 | moellons 180 mm, briquettes 40 mm, enduit platre 10 mm | 3.98812 | 3.51202 |  | 6.68167 | 0.23 | 1.59525 | 2.5 | 25afd9b5-9bbd-43b9-8fed-22435f7cc0c3--1026 | 25afd9b5-9bbd-43b9-8fed-22435f7cc0c3--1302 | WallQuantities - GrossSideAreaRight: 17.6375 m2; GrossSideAreaLeft: 16.1875 m2; NetSideAreaRight: 15.5675 m2; NetSideAreaLeft: 14.1175 m2; Allplan Attributes - Object Layer Attributes #2, Unité: m²; Object Layer Attributes #2, Métier: Maçonnerie; Object Layer Attributes #2, NOI_UUID: 25afd9b5-9bbd-43b9-8fed-22435f7cc0c3--1301; Object Layer Attributes #3, Unité: m²; Object Layer Attributes #3, Métier: Enduits et plâtrages; Object Layer Attributes #3, NOI_UUID: 25afd9b5-9bbd-43b9-8fed-22435f7cc0c3--1300; Object Layer Attributes #1, Matériau: moellons
 | r+2 | moellons 180 mm, briquettes 40 mm, enduit platre 10 mm | 4.05713 | 3.10493 |  | 6.80167 | 0.23 | 1.62285 | 2.5 | 25afd9b5-9bbd-43b9-8fed-22435f7cc0c3--1037 | 25afd9b5-9bbd-43b9-8fed-22435f7cc0c3--1297 | WallQuantities - GrossSideAreaRight: 17.9375 m2; GrossSideAreaLeft: 16.4875 m2; NetSideAreaRight: 13.7975 m2; NetSideAreaLeft: 12.3475 m2; Allplan Attributes - Object Layer Attributes #2, Unité: m²; Object Layer Attributes #2, Métier: Maçonnerie; Object Layer Attributes #2, NOI_UUID: 25afd9b5-9bbd-43b9-8fed-22435f7cc0c3--1298; Object Layer Attributes #3, Unité: m²; Object Layer Attributes #3, Métier: Enduits et plâtrages; Object Layer Attributes #3, NOI_UUID: 25afd9b5-9bbd-43b9-8fed-22435f7cc0c3--1299
 | r+2 | moellons 180 mm, briquettes 40 mm, enduit platre 10 mm | 4.05713 | 3.10493 |  | 6.80167 | 0.23 | 1.62285 | 2.5 | 25afd9b5-9bbd-43b9-8fed-22435f7cc0c3--1080 | 25afd9b5-9bbd-43b9-8fed-22435f7cc0c3--1250 | WallQuantities - GrossSideAreaRight: 17.9375 m2; GrossSideAreaLeft: 16.4875 m2; NetSideAreaRight: 13.7975 m2; NetSideAreaLeft: 12.3475 m2; Allplan Attributes - Object Layer Attributes #2, Unité: m²; Object Layer Attributes #2, Métier: Maçonnerie; Object Layer Attributes #2, NOI_UUID: 25afd9b5-9bbd-43b9-8fed-22435f7cc0c3--1249; Object Layer Attributes #3, Unité: m²; Object Layer Attributes #3, Métier: Enduits et plâtrages; Object Layer Attributes #3, NOI_UUID: 25afd9b5-9bbd-43b9-8fed-22435f7cc0c3--1248; Object Layer Attributes #1, Matériau: moellons
 | r+3 | moellons 180 mm, briquettes 40 mm, enduit platre 10 mm | 5.8765 | 5.78266 |  | 10.1067 | 0.23 | 2.3506 | 2.5 | a802760e-0c55-402d-9c1e-f3b9780ee869--696 | a802760e-0c55-402d-9c1e-f3b9780ee869--1241 | WallQuantities - GrossSideAreaRight: 25.675 m2; GrossSideAreaLeft: 25 m2; NetSideAreaRight: 25.267 m2; NetSideAreaLeft: 24.592 m2; Allplan Attributes - Object Layer Attributes #2, Unité: m²; Object Layer Attributes #2, Métier: Maçonnerie; Object Layer Attributes #2, NOI_UUID: a802760e-0c55-402d-9c1e-f3b9780ee869--1243; Object Layer Attributes #3, Unité: m²; Object Layer Attributes #3, Métier: Enduits et plâtrages; Object Layer Attributes #3, NOI_UUID: a802760e-0c55-402d-9c1e-f3b9780ee869--1242
 | r+3 | moellons 180 mm, briquettes 40 mm, enduit platre 10 mm | 11.1915 | 6.419 |  | 19.0267 | 0.23 | 4.4766 | 2.5 | a802760e-0c55-402d-9c1e-f3b9780ee869--698 | a802760e-0c55-402d-9c1e-f3b9780ee869--1232 | WallQuantities - GrossSideAreaRight: 49.175 m2; GrossSideAreaLeft: 46.7 m2; NetSideAreaRight: 28.425 m2; NetSideAreaLeft: 25.95 m2; Allplan Attributes - Object Layer Attributes #2, Unité: m²; Object Layer Attributes #2, Métier: Maçonnerie; Object Layer Attributes #2, NOI_UUID: a802760e-0c55-402d-9c1e-f3b9780ee869--1234; Object Layer Attributes #3, Unité: m²; Object Layer Attributes #3, Métier: Enduits et plâtrages; Object Layer Attributes #3, NOI_UUID: a802760e-0c55-402d-9c1e-f3b9780ee869--1233
 | r+3 | moellons 180 mm, briquettes 40 mm, enduit platre 10 mm | 5.7912 | 5.7912 |  | 10.0299 | 0.23 | 2.31648 | 2.5 | a802760e-0c55-402d-9c1e-f3b9780ee869--706 | a802760e-0c55-402d-9c1e-f3b9780ee869--1190 | WallQuantities - GrossSideAreaRight: 25.2248 m2; GrossSideAreaLeft: 24.9748 m2; NetSideAreaRight: 25.2248 m2; NetSideAreaLeft: 24.9748 m2; Allplan Attributes - Object Layer Attributes #2, Unité: m²; Object Layer Attributes #2, Métier: Maçonnerie; Object Layer Attributes #2, NOI_UUID: a802760e-0c55-402d-9c1e-f3b9780ee869--1189; Object Layer Attributes #3, Unité: m²; Object Layer Attributes #3, Métier: Enduits et plâtrages; Object Layer Attributes #3, NOI_UUID: a802760e-0c55-402d-9c1e-f3b9780ee869--1188
 | r+3 | moellons 180 mm, briquettes 40 mm, enduit platre 10 mm | 5.7912 | 5.7912 |  | 10.0299 | 0.23 | 2.31648 | 2.5 | a802760e-0c55-402d-9c1e-f3b9780ee869--717 | a802760e-0c55-402d-9c1e-f3b9780ee869--1192 | WallQuantities - GrossSideAreaRight: 25.2248 m2; GrossSideAreaLeft: 24.9748 m2; NetSideAreaRight: 25.2248 m2; NetSideAreaLeft: 24.9748 m2; Allplan Attributes - Object Layer Attributes #2, Unité: m²; Object Layer Attributes #2, Métier: Maçonnerie; Object Layer Attributes #2, NOI_UUID: a802760e-0c55-402d-9c1e-f3b9780ee869--1193; Object Layer Attributes #3, Unité: m²; Object Layer Attributes #3, Métier: Enduits et plâtrages; Object Layer Attributes #3, NOI_UUID: a802760e-0c55-402d-9c1e-f3b9780ee869--1194
 | r+3 | moellons 180 mm, briquettes 40 mm, enduit platre 10 mm | 7.9761 | 6.0717 |  | 13.3632 | 0.23 | 3.19044 | 2.5 | a802760e-0c55-402d-9c1e-f3b9780ee869--902 | a802760e-0c55-402d-9c1e-f3b9780ee869--1226 | WallQuantities - GrossSideAreaRight: 35.2741 m2; GrossSideAreaLeft: 32.375 m2; NetSideAreaRight: 26.995 m2; NetSideAreaLeft: 24.095 m2; Allplan Attributes - Object Layer Attributes #2, Unité: m²; Object Layer Attributes #2, Métier: Maçonnerie; Object Layer Attributes #2, NOI_UUID: a802760e-0c55-402d-9c1e-f3b9780ee869--1227; Object Layer Attributes #3, Unité: m²; Object Layer Attributes #3, Métier: Enduits et plâtrages; Object Layer Attributes #3, NOI_UUID: a802760e-0c55-402d-9c1e-f3b9780ee869--1228
 | r+3 | moellons 180 mm, briquettes 40 mm, enduit platre 10 mm | 5.79125 | 5.64267 |  | 10.03 | 0.23 | 2.3165 | 2.5 | a802760e-0c55-402d-9c1e-f3b9780ee869--901 | a802760e-0c55-402d-9c1e-f3b9780ee869--1165 | WallQuantities - GrossSideAreaRight: 25.225 m2; GrossSideAreaLeft: 24.975 m2; NetSideAreaRight: 24.579 m2; NetSideAreaLeft: 24.329 m2; Allplan Attributes - Object Layer Attributes #2, Unité: m²; Object Layer Attributes #2, Métier: Maçonnerie; Object Layer Attributes #2, NOI_UUID: a802760e-0c55-402d-9c1e-f3b9780ee869--1166; Object Layer Attributes #3, Unité: m²; Object Layer Attributes #3, Métier: Enduits et plâtrages; Object Layer Attributes #3, NOI_UUID: a802760e-0c55-402d-9c1e-f3b9780ee869--1167
 | r+3 | moellons 180 mm, briquettes 40 mm, enduit platre 10 mm | 5.7915 | 5.69766 |  | 10.0333 | 0.23 | 2.3166 | 2.5 | a802760e-0c55-402d-9c1e-f3b9780ee869--928 | a802760e-0c55-402d-9c1e-f3b9780ee869--1240 | WallQuantities - GrossSideAreaRight: 25.225 m2; GrossSideAreaLeft: 25 m2; NetSideAreaRight: 24.817 m2; NetSideAreaLeft: 24.592 m2; Allplan Attributes - Object Layer Attributes #2, Unité: m²; Object Layer Attributes #2, Métier: Maçonnerie; Object Layer Attributes #2, NOI_UUID: a802760e-0c55-402d-9c1e-f3b9780ee869--1238; Object Layer Attributes #3, Unité: m²; Object Layer Attributes #3, Métier: Enduits et plâtrages; Object Layer Attributes #3, NOI_UUID: a802760e-0c55-402d-9c1e-f3b9780ee869--1239
 | r+3 | moellons 180 mm, briquettes 40 mm, enduit platre 10 mm | 11.2765 | 6.504 |  | 19.1 | 0.23 | 4.5106 | 2.5 | a802760e-0c55-402d-9c1e-f3b9780ee869--839 | a802760e-0c55-402d-9c1e-f3b9780ee869--1237 | WallQuantities - GrossSideAreaRight: 49.625 m2; GrossSideAreaLeft: 46.7 m2; NetSideAreaRight: 28.875 m2; NetSideAreaLeft: 25.95 m2; Allplan Attributes - Object Layer Attributes #2, Unité: m²; Object Layer Attributes #2, Métier: Maçonnerie; Object Layer Attributes #2, NOI_UUID: a802760e-0c55-402d-9c1e-f3b9780ee869--1236; Object Layer Attributes #3, Unité: m²; Object Layer Attributes #3, Métier: Enduits et plâtrages; Object Layer Attributes #3, NOI_UUID: a802760e-0c55-402d-9c1e-f3b9780ee869--1235
 | r+3 | moellons 180 mm, briquettes 40 mm, enduit platre 10 mm | 5.7912 | 5.16652 |  | 10.0299 | 0.23 | 2.31648 | 2.5 | a802760e-0c55-402d-9c1e-f3b9780ee869--927 | a802760e-0c55-402d-9c1e-f3b9780ee869--1246 | WallQuantities - GrossSideAreaRight: 25.2248 m2; GrossSideAreaLeft: 24.9748 m2; NetSideAreaRight: 22.5088 m2; NetSideAreaLeft: 22.2588 m2; Allplan Attributes - Object Layer Attributes #2, Unité: m²; Object Layer Attributes #2, Métier: Maçonnerie; Object Layer Attributes #2, NOI_UUID: a802760e-0c55-402d-9c1e-f3b9780ee869--1245; Object Layer Attributes #3, Unité: m²; Object Layer Attributes #3, Métier: Enduits et plâtrages; Object Layer Attributes #3, NOI_UUID: a802760e-0c55-402d-9c1e-f3b9780ee869--1244
 | r+3 | moellons 180 mm, briquettes 40 mm, enduit platre 10 mm | 4.05712 | 3.10492 |  | 6.80167 | 0.23 | 1.62285 | 2.5 | a802760e-0c55-402d-9c1e-f3b9780ee869--941 | a802760e-0c55-402d-9c1e-f3b9780ee869--1211 | WallQuantities - GrossSideAreaRight: 17.9375 m2; GrossSideAreaLeft: 16.4875 m2; NetSideAreaRight: 13.7975 m2; NetSideAreaLeft: 12.3475 m2; Allplan Attributes - Object Layer Attributes #2, Unité: m²; Object Layer Attributes #2, Métier: Maçonnerie; Object Layer Attributes #2, NOI_UUID: a802760e-0c55-402d-9c1e-f3b9780ee869--1213; Object Layer Attributes #3, Unité: m²; Object Layer Attributes #3, Métier: Enduits et plâtrages; Object Layer Attributes #3, NOI_UUID: a802760e-0c55-402d-9c1e-f3b9780ee869--1212
 | r+3 | moellons 180 mm, briquettes 40 mm, enduit platre 10 mm | 3.98805 | 3.51195 |  | 6.68161 | 0.23 | 1.59522 | 2.5 | a802760e-0c55-402d-9c1e-f3b9780ee869--949 | a802760e-0c55-402d-9c1e-f3b9780ee869--1225 | WallQuantities - GrossSideAreaRight: 17.6371 m2; GrossSideAreaLeft: 16.1875 m2; NetSideAreaRight: 15.5675 m2; NetSideAreaLeft: 14.1175 m2; Allplan Attributes - Object Layer Attributes #2, Unité: m²; Object Layer Attributes #2, Métier: Maçonnerie; Object Layer Attributes #2, NOI_UUID: a802760e-0c55-402d-9c1e-f3b9780ee869--1224; Object Layer Attributes #3, Unité: m²; Object Layer Attributes #3, Métier: Enduits et plâtrages; Object Layer Attributes #3, NOI_UUID: a802760e-0c55-402d-9c1e-f3b9780ee869--1223
 | r+3 | moellons 180 mm, briquettes 40 mm, enduit platre 10 mm | 4.07963 | 3.12743 |  | 6.92167 | 0.23 | 1.63185 | 2.5 | a802760e-0c55-402d-9c1e-f3b9780ee869--960 | a802760e-0c55-402d-9c1e-f3b9780ee869--1220 | WallQuantities - GrossSideAreaRight: 17.9375 m2; GrossSideAreaLeft: 16.9375 m2; NetSideAreaRight: 13.7975 m2; NetSideAreaLeft: 12.7975 m2; Allplan Attributes - Object Layer Attributes #2, Unité: m²; Object Layer Attributes #2, Métier: Maçonnerie; Object Layer Attributes #2, NOI_UUID: a802760e-0c55-402d-9c1e-f3b9780ee869--1221; Object Layer Attributes #3, Unité: m²; Object Layer Attributes #3, Métier: Enduits et plâtrages; Object Layer Attributes #3, NOI_UUID: a802760e-0c55-402d-9c1e-f3b9780ee869--1222
 | r+3 | moellons 180 mm, briquettes 40 mm, enduit platre 10 mm | 4.05713 | 3.10493 |  | 6.80167 | 0.23 | 1.62285 | 2.5 | a802760e-0c55-402d-9c1e-f3b9780ee869--1003 | a802760e-0c55-402d-9c1e-f3b9780ee869--1173 | WallQuantities - GrossSideAreaRight: 17.9375 m2; GrossSideAreaLeft: 16.4875 m2; NetSideAreaRight: 13.7975 m2; NetSideAreaLeft: 12.3475 m2; Allplan Attributes - Object Layer Attributes #2, Unité: m²; Object Layer Attributes #2, Métier: Maçonnerie; Object Layer Attributes #2, NOI_UUID: a802760e-0c55-402d-9c1e-f3b9780ee869--1172; Object Layer Attributes #3, Unité: m²; Object Layer Attributes #3, Métier: Enduits et plâtrages; Object Layer Attributes #3, NOI_UUID: a802760e-0c55-402d-9c1e-f3b9780ee869--1171
 | r+3 | moellons 180 mm, briquettes 40 mm, enduit platre 10 mm | 11.2542 | 6.48175 |  | 18.9833 | 0.23 | 4.5017 | 2.5 | a802760e-0c55-402d-9c1e-f3b9780ee869--719 | a802760e-0c55-402d-9c1e-f3b9780ee869--1229 | WallQuantities - GrossSideAreaRight: 49.625 m2; GrossSideAreaLeft: 46.275 m2; NetSideAreaRight: 28.875 m2; NetSideAreaLeft: 25.525 m2; Allplan Attributes - Object Layer Attributes #2, Unité: m²; Object Layer Attributes #2, Métier: Maçonnerie; Object Layer Attributes #2, NOI_UUID: a802760e-0c55-402d-9c1e-f3b9780ee869--1231; Object Layer Attributes #3, Unité: m²; Object Layer Attributes #3, Métier: Enduits et plâtrages; Object Layer Attributes #3, NOI_UUID: a802760e-0c55-402d-9c1e-f3b9780ee869--1230
 | r+3 | moellons 180 mm | 4.5405 | 4.5405 | 25.225 | 10.09 | 0.18 | 1.8162 | 2.5 | a802760e-0c55-402d-9c1e-f3b9780ee869--763 | a802760e-0c55-402d-9c1e-f3b9780ee869--1169 | Allplan Attributes - Object Layer Attributes #1, Matériau: moellons
 | r+3 | moellons 180 mm | 4.5405 | 4.5405 | 25.225 | 10.09 | 0.18 | 1.8162 | 2.5 | a802760e-0c55-402d-9c1e-f3b9780ee869--777 | a802760e-0c55-402d-9c1e-f3b9780ee869--1170
 | r+3 | moellons 180 mm | 4.5405 | 4.5405 | 25.225 | 10.09 | 0.18 | 1.8162 | 2.5 | a802760e-0c55-402d-9c1e-f3b9780ee869--781 | a802760e-0c55-402d-9c1e-f3b9780ee869--1187
 | r+3 | moellons 180 mm | 4.5405 | 4.5405 | 25.225 | 10.09 | 0.18 | 1.8162 | 2.5 | a802760e-0c55-402d-9c1e-f3b9780ee869--785 | a802760e-0c55-402d-9c1e-f3b9780ee869--1195
 | r+3 | moellons 180 mm | 4.518 | 4.518 | 25.1 | 10.04 | 0.18 | 1.8072 | 2.5 | a802760e-0c55-402d-9c1e-f3b9780ee869--789 | a802760e-0c55-402d-9c1e-f3b9780ee869--1191
 | r+3 | moellons 180 mm | 4.5405 | 4.5405 | 25.225 | 10.09 | 0.18 | 1.8162 | 2.5 | a802760e-0c55-402d-9c1e-f3b9780ee869--793 | a802760e-0c55-402d-9c1e-f3b9780ee869--1179
 | r+3 | moellons 180 mm | 4.5405 | 4.5405 | 25.225 | 10.09 | 0.18 | 1.8162 | 2.5 | a802760e-0c55-402d-9c1e-f3b9780ee869--797 | a802760e-0c55-402d-9c1e-f3b9780ee869--1210
 | r+3 | moellons 180 mm | 4.5405 | 4.5405 | 25.225 | 10.09 | 0.18 | 1.8162 | 2.5 | a802760e-0c55-402d-9c1e-f3b9780ee869--801 | a802760e-0c55-402d-9c1e-f3b9780ee869--1209
 | r+3 | moellons 180 mm | 1.638 | 1.638 | 9.1 | 3.64 | 0.18 | 0.6552 | 2.5 | a802760e-0c55-402d-9c1e-f3b9780ee869--806 | a802760e-0c55-402d-9c1e-f3b9780ee869--1185
 | r+3 | moellons 180 mm | 1.638 | 1.638 | 9.1 | 3.64 | 0.18 | 0.6552 | 2.5 | a802760e-0c55-402d-9c1e-f3b9780ee869--811 | a802760e-0c55-402d-9c1e-f3b9780ee869--1178
 | r+3 | moellons 180 mm | 2.9025 | 2.9025 | 16.125 | 6.45 | 0.18 | 1.161 | 2.5 | a802760e-0c55-402d-9c1e-f3b9780ee869--817 | a802760e-0c55-402d-9c1e-f3b9780ee869--1186
 | r+3 | moellons 180 mm | 0.225 | 0.225 | 1.25 | 0.5 | 0.18 | 0.09 | 2.5 | a802760e-0c55-402d-9c1e-f3b9780ee869--820 | a802760e-0c55-402d-9c1e-f3b9780ee869--1183
2 x  | r+3 | moellons 180 mm | 1.3365 | 1.3365 | 7.425 | 2.97 | 0.18 | 0.5346 | 2.5 | a802760e-0c55-402d-9c1e-f3b9780ee869--822 | a802760e-0c55-402d-9c1e-f3b9780ee869--1176
 | r+3 | moellons 180 mm | 0.144 | 0.144 | 0.8 | 0.32 | 0.18 | 0.0576 | 2.5 | a802760e-0c55-402d-9c1e-f3b9780ee869--824 | a802760e-0c55-402d-9c1e-f3b9780ee869--1184
 | r+3 | moellons 180 mm | 2.9025 | 2.9025 | 16.125 | 6.45 | 0.18 | 1.161 | 2.5 | a802760e-0c55-402d-9c1e-f3b9780ee869--826 | a802760e-0c55-402d-9c1e-f3b9780ee869--1180
 | r+3 | moellons 180 mm | 0.225 | 0.225 | 1.25 | 0.5 | 0.18 | 0.09 | 2.5 | a802760e-0c55-402d-9c1e-f3b9780ee869--828 | a802760e-0c55-402d-9c1e-f3b9780ee869--1181
2 x  | r+3 | moellons 180 mm | 1.3365 | 1.3365 | 7.425 | 2.97 | 0.18 | 0.5346 | 2.5 | a802760e-0c55-402d-9c1e-f3b9780ee869--830 | a802760e-0c55-402d-9c1e-f3b9780ee869--1174
 | r+3 | moellons 180 mm | 0.144 | 0.144 | 0.8 | 0.32 | 0.18 | 0.0576 | 2.5 | a802760e-0c55-402d-9c1e-f3b9780ee869--832 | a802760e-0c55-402d-9c1e-f3b9780ee869--1182
 | r+3 | moellons 180 mm | 1.66502 | 1.66502 | 9.2501 | 3.70004 | 0.18 | 0.666007 | 2.5 | a802760e-0c55-402d-9c1e-f3b9780ee869--805 | a802760e-0c55-402d-9c1e-f3b9780ee869--1177
 | r+3 | moellons 180 mm | 1.66502 | 1.66502 | 9.2501 | 3.70004 | 0.18 | 0.666007 | 2.5 | a802760e-0c55-402d-9c1e-f3b9780ee869--810 | a802760e-0c55-402d-9c1e-f3b9780ee869--1175
 | r+3 | moellons 180 mm | 4.4955 | 4.4955 | 24.975 | 9.99 | 0.18 | 1.7982 | 2.5 | a802760e-0c55-402d-9c1e-f3b9780ee869--847 | a802760e-0c55-402d-9c1e-f3b9780ee869--1218
 | r+3 | moellons 180 mm | 4.5405 | 4.5405 | 25.225 | 10.09 | 0.18 | 1.8162 | 2.5 | a802760e-0c55-402d-9c1e-f3b9780ee869--856 | a802760e-0c55-402d-9c1e-f3b9780ee869--1219
 | r+3 | moellons 180 mm | 4.5405 | 4.5405 | 25.225 | 10.09 | 0.18 | 1.8162 | 2.5 | a802760e-0c55-402d-9c1e-f3b9780ee869--858 | a802760e-0c55-402d-9c1e-f3b9780ee869--1214
 | r+3 | moellons 180 mm | 4.5405 | 4.5405 | 25.225 | 10.09 | 0.18 | 1.8162 | 2.5 | a802760e-0c55-402d-9c1e-f3b9780ee869--860 | a802760e-0c55-402d-9c1e-f3b9780ee869--1216
 | r+3 | moellons 180 mm | 1.638 | 1.638 | 9.1 | 3.64 | 0.18 | 0.6552 | 2.5 | a802760e-0c55-402d-9c1e-f3b9780ee869--863 | a802760e-0c55-402d-9c1e-f3b9780ee869--1203
 | r+3 | moellons 180 mm | 2.9025 | 2.9025 | 16.125 | 6.45 | 0.18 | 1.161 | 2.5 | a802760e-0c55-402d-9c1e-f3b9780ee869--867 | a802760e-0c55-402d-9c1e-f3b9780ee869--1202
 | r+3 | moellons 180 mm | 0.225 | 0.225 | 1.25 | 0.5 | 0.18 | 0.09 | 2.5 | a802760e-0c55-402d-9c1e-f3b9780ee869--869 | a802760e-0c55-402d-9c1e-f3b9780ee869--1205
2 x  | r+3 | moellons 180 mm | 1.3365 | 1.3365 | 7.425 | 2.97 | 0.18 | 0.5346 | 2.5 | a802760e-0c55-402d-9c1e-f3b9780ee869--871 | a802760e-0c55-402d-9c1e-f3b9780ee869--1207
 | r+3 | moellons 180 mm | 0.144 | 0.144 | 0.8 | 0.32 | 0.18 | 0.0576 | 2.5 | a802760e-0c55-402d-9c1e-f3b9780ee869--873 | a802760e-0c55-402d-9c1e-f3b9780ee869--1204
 | r+3 | moellons 180 mm | 1.66502 | 1.66502 | 9.2501 | 3.70004 | 0.18 | 0.666007 | 2.5 | a802760e-0c55-402d-9c1e-f3b9780ee869--862 | a802760e-0c55-402d-9c1e-f3b9780ee869--1206
 | r+3 | moellons 20 mm | 0.009 | 0.009 | 0.05 | 0.02 | 0.18 | 0.0036 | 2.5 | a802760e-0c55-402d-9c1e-f3b9780ee869--751 | a802760e-0c55-402d-9c1e-f3b9780ee869--1197 | Allplan Attributes - Object Layer Attributes #1, Matériau: moellons
 | r+3 | moellons 20.0776 mm | 0.0090349 | 0.0090349 | 0.0501939 | 0.02008 | 0.18 | 0.00361396 | 2.5 | a802760e-0c55-402d-9c1e-f3b9780ee869--749 | a802760e-0c55-402d-9c1e-f3b9780ee869--1168
 | r+3 | moellons 20 mm | 0.009 | 0.009 | 0.05 | 0.02 | 0.18 | 0.0036 | 2.5 | a802760e-0c55-402d-9c1e-f3b9780ee869--753 | a802760e-0c55-402d-9c1e-f3b9780ee869--1201
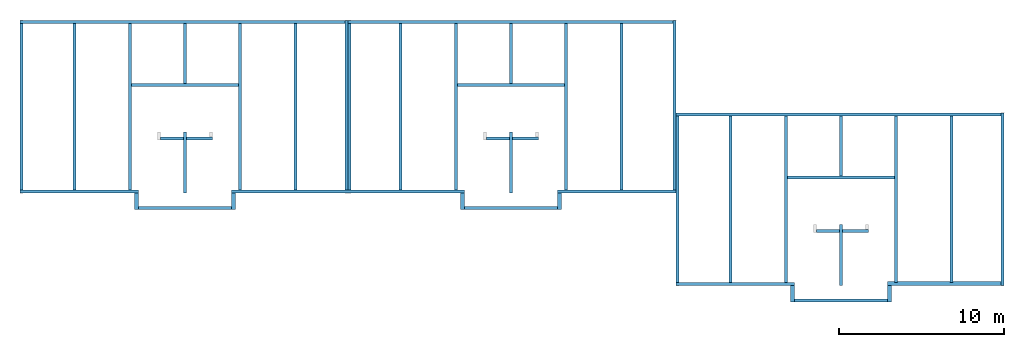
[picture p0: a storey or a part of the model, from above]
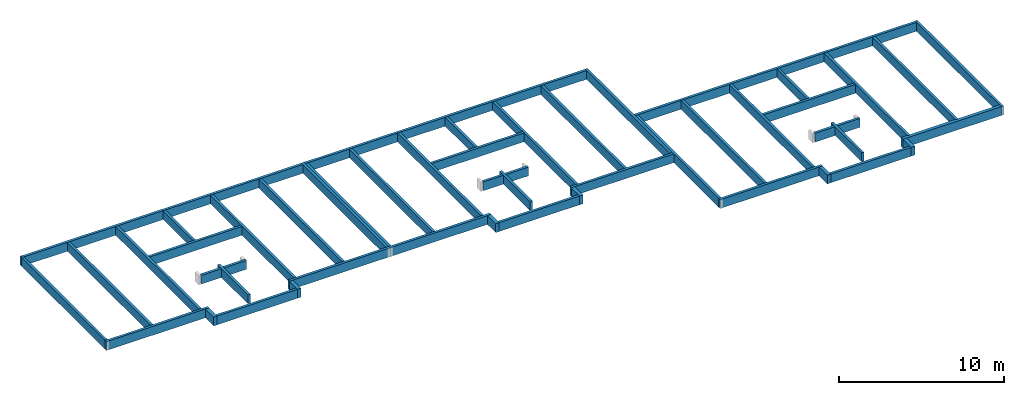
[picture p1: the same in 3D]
Properties of the parts of a building model (IFC2X3), part 3 of 3

# IfcWallStandardCase (300)
Name | In | Material | GrossVolume (m3) | NetVolume (m3) | GrossSideArea (m2) = NetSideArea (m2) | NominalLength (m) | NominalWidth (m) | GrossFootprintArea (m2) | NominalHeight (m) | NOI_UUID | Object Layer Attributes #1, NOI_UUID
 | r+3 | moellons 20 mm | 0.009 | 0.009 | 0.05 | 0.02 | 0.18 | 0.0036 | 2.5 | a802760e-0c55-402d-9c1e-f3b9780ee869--755 | a802760e-0c55-402d-9c1e-f3b9780ee869--1196
 | r+3 | moellons 20 mm | 0.009 | 0.009 | 0.05 | 0.02 | 0.18 | 0.0036 | 2.5 | a802760e-0c55-402d-9c1e-f3b9780ee869--757 | a802760e-0c55-402d-9c1e-f3b9780ee869--1200
 | r+3 | moellons 20.1628 mm | 0.00907326 | 0.00907326 | 0.050407 | 0.02016 | 0.18 | 0.0036293 | 2.5 | a802760e-0c55-402d-9c1e-f3b9780ee869--759 | a802760e-0c55-402d-9c1e-f3b9780ee869--1198
 | r+3 | moellons 20.1628 mm | 0.00907326 | 0.00907326 | 0.050407 | 0.02016 | 0.18 | 0.0036293 | 2.5 | a802760e-0c55-402d-9c1e-f3b9780ee869--761 | a802760e-0c55-402d-9c1e-f3b9780ee869--1199
 | r+3 | moellons 20.0776 mm | 0.0090349 | 0.0090349 | 0.0501939 | 0.02008 | 0.18 | 0.00361396 | 2.5 | a802760e-0c55-402d-9c1e-f3b9780ee869--841 | a802760e-0c55-402d-9c1e-f3b9780ee869--1217
 | r+3 | moellons 20 mm | 0.009 | 0.009 | 0.05 | 0.02 | 0.18 | 0.0036 | 2.5 | a802760e-0c55-402d-9c1e-f3b9780ee869--843 | a802760e-0c55-402d-9c1e-f3b9780ee869--1208
 | r+3 | moellons 20.1628 mm | 0.00907326 | 0.00907326 | 0.050407 | 0.02016 | 0.18 | 0.0036293 | 2.5 | a802760e-0c55-402d-9c1e-f3b9780ee869--845 | a802760e-0c55-402d-9c1e-f3b9780ee869--1215
